VERSION 5.7 ;
  DIVIDERCHAR "/" ;
  BUSBITCHARS "[]" ;
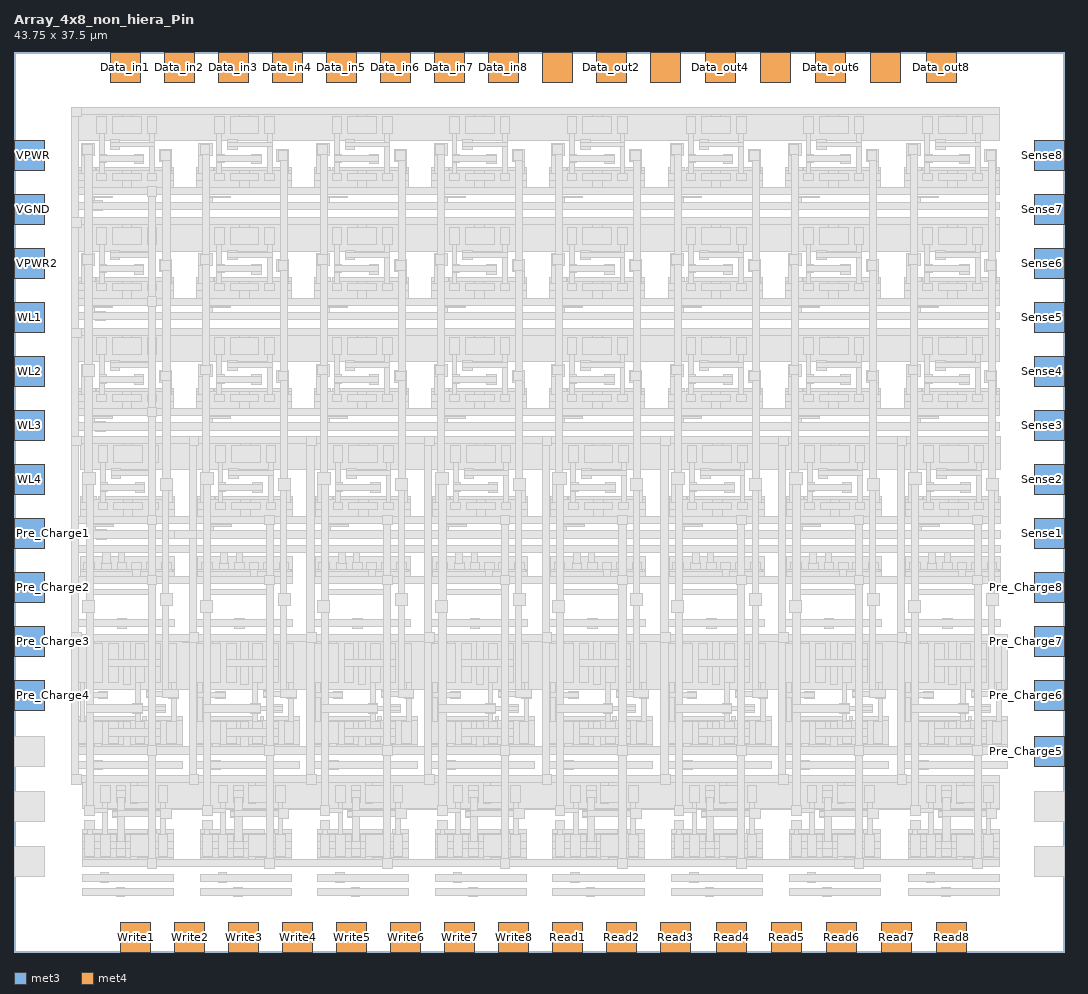
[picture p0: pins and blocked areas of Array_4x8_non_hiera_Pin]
MACRO Array_4x8_non_hiera_Pin
  CLASS BLOCK ;
  FOREIGN Array_4x8_non_hiera_Pin ;
  ORIGIN 2.4 2.3 ;
  SIZE 43.75 BY 37.5 ;
  PIN VPWR
    USE POWER ;
    PORT
      LAYER met3 ;
        RECT -2.4 30.25 -1.15 31.5 ;
    END
  END VPWR
  PIN VGND
    USE GROUND ;
    PORT
      LAYER met3 ;
        RECT -2.4 28 -1.15 29.25 ;
    END
  END VGND
  PIN VPWR2
    USE POWER ;
    PORT
      LAYER met3 ;
        RECT -2.4 25.75 -1.15 27 ;
    END
  END VPWR2
  PIN WL1
    PORT
      LAYER met3 ;
        RECT -2.4 23.5 -1.15 24.75 ;
    END
  END WL1
  PIN WL2
    PORT
      LAYER met3 ;
        RECT -2.4 21.25 -1.15 22.5 ;
    END
  END WL2
  PIN WL3
    PORT
      LAYER met3 ;
        RECT -2.4 19 -1.15 20.25 ;
    END
  END WL3
  PIN WL4
    PORT
      LAYER met3 ;
        RECT -2.4 16.75 -1.15 18 ;
    END
  END WL4
  PIN Pre_Charge1
    PORT
      LAYER met3 ;
        RECT -2.4 14.5 -1.15 15.75 ;
    END
  END Pre_Charge1
  PIN Pre_Charge2
    PORT
      LAYER met3 ;
        RECT -2.4 12.25 -1.15 13.5 ;
    END
  END Pre_Charge2
  PIN Pre_Charge3
    PORT
      LAYER met3 ;
        RECT -2.4 10 -1.15 11.25 ;
    END
  END Pre_Charge3
  PIN Pre_Charge4
    PORT
      LAYER met3 ;
        RECT -2.4 7.75 -1.15 9 ;
    END
  END Pre_Charge4
  PIN Pre_Charge5
    PORT
      LAYER met3 ;
        RECT 40.1 5.45 41.35 6.7 ;
    END
  END Pre_Charge5
  PIN Pre_Charge6
    PORT
      LAYER met3 ;
        RECT 40.1 7.75 41.35 9 ;
    END
  END Pre_Charge6
  PIN Pre_Charge7
    PORT
      LAYER met3 ;
        RECT 40.1 10 41.35 11.25 ;
    END
  END Pre_Charge7
  PIN Pre_Charge8
    PORT
      LAYER met3 ;
        RECT 40.1 12.25 41.35 13.5 ;
    END
  END Pre_Charge8
  PIN Sense1
    PORT
      LAYER met3 ;
        RECT 40.1 14.5 41.35 15.75 ;
    END
  END Sense1
  PIN Sense2
    PORT
      LAYER met3 ;
        RECT 40.1 16.75 41.35 18 ;
    END
  END Sense2
  PIN Sense3
    PORT
      LAYER met3 ;
        RECT 40.1 19 41.35 20.25 ;
    END
  END Sense3
  PIN Sense4
    PORT
      LAYER met3 ;
        RECT 40.1 21.25 41.35 22.5 ;
    END
  END Sense4
  PIN Sense5
    PORT
      LAYER met3 ;
        RECT 40.1 23.5 41.35 24.75 ;
    END
  END Sense5
  PIN Sense6
    PORT
      LAYER met3 ;
        RECT 40.1 25.75 41.35 27 ;
    END
  END Sense6
  PIN Sense7
    PORT
      LAYER met3 ;
        RECT 40.1 28 41.35 29.25 ;
    END
  END Sense7
  PIN Sense8
    PORT
      LAYER met3 ;
        RECT 40.1 30.25 41.35 31.5 ;
    END
  END Sense8
  PIN Write2
    PORT
      LAYER met4 ;
        RECT 4.3 -2.3 5.55 -1.05 ;
    END
  END Write2
  PIN Write3
    PORT
      LAYER met4 ;
        RECT 6.55 -2.3 7.8 -1.05 ;
    END
  END Write3
  PIN Write4
    PORT
      LAYER met4 ;
        RECT 8.8 -2.3 10.05 -1.05 ;
    END
  END Write4
  PIN Write5
    PORT
      LAYER met4 ;
        RECT 11.05 -2.3 12.3 -1.05 ;
    END
  END Write5
  PIN Write6
    PORT
      LAYER met4 ;
        RECT 13.3 -2.3 14.55 -1.05 ;
    END
  END Write6
  PIN Write7
    PORT
      LAYER met4 ;
        RECT 15.55 -2.3 16.8 -1.05 ;
    END
  END Write7
  PIN Write8
    PORT
      LAYER met4 ;
        RECT 17.8 -2.3 19.05 -1.05 ;
    END
  END Write8
  PIN Read1
    PORT
      LAYER met4 ;
        RECT 20.05 -2.3 21.3 -1.05 ;
    END
  END Read1
  PIN Read2
    PORT
      LAYER met4 ;
        RECT 22.3 -2.3 23.55 -1.05 ;
    END
  END Read2
  PIN Read3
    PORT
      LAYER met4 ;
        RECT 24.55 -2.3 25.8 -1.05 ;
    END
  END Read3
  PIN Read4
    PORT
      LAYER met4 ;
        RECT 26.85 -2.3 28.1 -1.05 ;
    END
  END Read4
  PIN Read5
    PORT
      LAYER met4 ;
        RECT 29.15 -2.3 30.4 -1.05 ;
    END
  END Read5
  PIN Read6
    PORT
      LAYER met4 ;
        RECT 31.45 -2.3 32.7 -1.05 ;
    END
  END Read6
  PIN Read7
    PORT
      LAYER met4 ;
        RECT 33.75 -2.3 35 -1.05 ;
    END
  END Read7
  PIN Read8
    PORT
      LAYER met4 ;
        RECT 36.05 -2.3 37.3 -1.05 ;
    END
  END Read8
  PIN Data_in3
    PORT
      LAYER met4 ;
        RECT 6.1 33.95 7.35 35.2 ;
    END
  END Data_in3
  PIN Data_in5
    PORT
      LAYER met4 ;
        RECT 10.6 33.95 11.85 35.2 ;
    END
  END Data_in5
  PIN Data_in6
    PORT
      LAYER met4 ;
        RECT 12.85 33.95 14.1 35.2 ;
    END
  END Data_in6
  PIN Data_in7
    PORT
      LAYER met4 ;
        RECT 15.1 33.95 16.35 35.2 ;
    END
  END Data_in7
  PIN Data_in8
    PORT
      LAYER met4 ;
        RECT 17.35 33.95 18.6 35.2 ;
    END
  END Data_in8
  PIN Data_out1
    PORT
      LAYER met4 ;
        RECT 19.6 33.95 20.85 35.2 ;
    END
  END Data_out1
  PIN Data_out2
    PORT
      LAYER met4 ;
        RECT 21.85 33.95 23.1 35.2 ;
    END
  END Data_out2
  PIN Data_out3
    PORT
      LAYER met4 ;
        RECT 24.1 33.95 25.35 35.2 ;
    END
  END Data_out3
  PIN Data_out4
    PORT
      LAYER met4 ;
        RECT 26.4 33.95 27.65 35.2 ;
    END
  END Data_out4
  PIN Data_out5
    PORT
      LAYER met4 ;
        RECT 28.7 33.95 29.95 35.2 ;
    END
  END Data_out5
  PIN Data_out6
    PORT
      LAYER met4 ;
        RECT 31 33.95 32.25 35.2 ;
    END
  END Data_out6
  PIN Data_out8
    PORT
      LAYER met4 ;
        RECT 35.6 33.95 36.85 35.2 ;
    END
  END Data_out8
  PIN Write1
    PORT
      LAYER met4 ;
        RECT 2.05 -2.3 3.3 -1.05 ;
    END
  END Write1
  PIN Data_in1
    PORT
      LAYER met4 ;
        RECT 1.6 33.95 2.85 35.2 ;
    END
  END Data_in1
  PIN Data_in2
    PORT
      LAYER met4 ;
        RECT 3.85 33.95 5.1 35.2 ;
    END
  END Data_in2
  PIN Data_in4
    PORT
      LAYER met4 ;
        RECT 8.35 33.95 9.6 35.2 ;
    END
  END Data_in4
  PIN Data_out7
    PORT
      LAYER met4 ;
        RECT 33.3 33.95 34.55 35.2 ;
    END
  END Data_out7
  OBS
      LAYER nwell ;
        RECT 0.3 31.5 38.65 32.8 ;
      LAYER pwell ;
        RECT 0.3 30.25 1 30.4 ;
        RECT 1.05 30.25 4.25 30.4 ;
        RECT 0.3 29.55 4.25 30.25 ;
        RECT 5.2 30.25 5.9 30.4 ;
        RECT 5.95 30.25 9.15 30.4 ;
        RECT 5.2 29.55 9.15 30.25 ;
        RECT 10.1 30.25 10.8 30.4 ;
        RECT 10.85 30.25 14.05 30.4 ;
        RECT 10.1 29.55 14.05 30.25 ;
        RECT 15 30.25 15.7 30.4 ;
        RECT 15.75 30.25 18.95 30.4 ;
        RECT 15 29.55 18.95 30.25 ;
        RECT 19.9 30.25 20.6 30.4 ;
        RECT 20.65 30.25 23.85 30.4 ;
        RECT 19.9 29.55 23.85 30.25 ;
        RECT 24.85 30.25 25.55 30.4 ;
        RECT 25.6 30.25 28.8 30.4 ;
        RECT 24.85 29.55 28.8 30.25 ;
        RECT 29.75 30.25 30.45 30.4 ;
        RECT 30.5 30.25 33.7 30.4 ;
        RECT 29.75 29.55 33.7 30.25 ;
        RECT 34.7 30.25 35.4 30.4 ;
        RECT 35.45 30.25 38.65 30.4 ;
        RECT 34.7 29.55 38.65 30.25 ;
        RECT 0.3 29.3 38.65 29.55 ;
        RECT 0.3 29.25 2.8 29.3 ;
        RECT 3.4 29.25 7.7 29.3 ;
        RECT 8.3 29.25 12.6 29.3 ;
        RECT 13.2 29.25 17.5 29.3 ;
        RECT 18.1 29.25 22.4 29.3 ;
        RECT 23 29.25 27.35 29.3 ;
        RECT 27.95 29.25 32.25 29.3 ;
        RECT 32.85 29.25 37.2 29.3 ;
        RECT 37.8 29.25 38.65 29.3 ;
        RECT 0.7 29.15 1.7 29.2 ;
        RECT 5.6 29.15 6.6 29.2 ;
        RECT 10.5 29.15 11.5 29.2 ;
        RECT 15.4 29.15 16.4 29.2 ;
        RECT 20.3 29.15 21.3 29.2 ;
        RECT 25.25 29.15 26.25 29.2 ;
        RECT 30.15 29.15 31.15 29.2 ;
        RECT 35.1 29.15 36.1 29.2 ;
        RECT 0.8 28.9 0.95 29.15 ;
        RECT 5.7 28.9 5.85 29.15 ;
        RECT 10.6 28.9 10.75 29.15 ;
        RECT 15.5 28.9 15.65 29.15 ;
        RECT 20.4 28.9 20.55 29.15 ;
        RECT 25.35 28.9 25.5 29.15 ;
        RECT 30.25 28.9 30.4 29.15 ;
        RECT 35.2 28.9 35.35 29.15 ;
      LAYER nwell ;
        RECT 0.3 26.9 38.65 28.2 ;
      LAYER pwell ;
        RECT 0.3 25.65 1 25.8 ;
        RECT 1.05 25.65 4.25 25.8 ;
        RECT 0.3 24.95 4.25 25.65 ;
        RECT 5.2 25.65 5.9 25.8 ;
        RECT 5.95 25.65 9.15 25.8 ;
        RECT 5.2 24.95 9.15 25.65 ;
        RECT 10.1 25.65 10.8 25.8 ;
        RECT 10.85 25.65 14.05 25.8 ;
        RECT 10.1 24.95 14.05 25.65 ;
        RECT 15 25.65 15.7 25.8 ;
        RECT 15.75 25.65 18.95 25.8 ;
        RECT 15 24.95 18.95 25.65 ;
        RECT 19.9 25.65 20.6 25.8 ;
        RECT 20.65 25.65 23.85 25.8 ;
        RECT 19.9 24.95 23.85 25.65 ;
        RECT 24.85 25.65 25.55 25.8 ;
        RECT 25.6 25.65 28.8 25.8 ;
        RECT 24.85 24.95 28.8 25.65 ;
        RECT 29.75 25.65 30.45 25.8 ;
        RECT 30.5 25.65 33.7 25.8 ;
        RECT 29.75 24.95 33.7 25.65 ;
        RECT 34.7 25.65 35.4 25.8 ;
        RECT 35.45 25.65 38.65 25.8 ;
        RECT 34.7 24.95 38.65 25.65 ;
        RECT 0.3 24.7 38.65 24.95 ;
        RECT 0.3 24.65 2.8 24.7 ;
        RECT 3.4 24.65 7.7 24.7 ;
        RECT 8.3 24.65 12.6 24.7 ;
        RECT 13.2 24.65 17.5 24.7 ;
        RECT 18.1 24.65 22.4 24.7 ;
        RECT 23 24.65 27.35 24.7 ;
        RECT 27.95 24.65 32.25 24.7 ;
        RECT 32.85 24.65 37.2 24.7 ;
        RECT 37.8 24.65 38.65 24.7 ;
        RECT 0.7 24.55 1.7 24.6 ;
        RECT 5.6 24.55 6.6 24.6 ;
        RECT 10.5 24.55 11.5 24.6 ;
        RECT 15.4 24.55 16.4 24.6 ;
        RECT 20.3 24.55 21.3 24.6 ;
        RECT 25.25 24.55 26.25 24.6 ;
        RECT 30.15 24.55 31.15 24.6 ;
        RECT 35.1 24.55 36.1 24.6 ;
        RECT 0.8 24.3 0.95 24.55 ;
        RECT 5.7 24.3 5.85 24.55 ;
        RECT 10.6 24.3 10.75 24.55 ;
        RECT 15.5 24.3 15.65 24.55 ;
        RECT 20.4 24.3 20.55 24.55 ;
        RECT 25.35 24.3 25.5 24.55 ;
        RECT 30.25 24.3 30.4 24.55 ;
        RECT 35.2 24.3 35.35 24.55 ;
      LAYER nwell ;
        RECT 0.3 22.3 38.65 23.6 ;
      LAYER pwell ;
        RECT 0.3 21.05 1 21.2 ;
        RECT 1.05 21.05 4.25 21.2 ;
        RECT 0.3 20.35 4.25 21.05 ;
        RECT 5.2 21.05 5.9 21.2 ;
        RECT 5.95 21.05 9.15 21.2 ;
        RECT 5.2 20.35 9.15 21.05 ;
        RECT 10.1 21.05 10.8 21.2 ;
        RECT 10.85 21.05 14.05 21.2 ;
        RECT 10.1 20.35 14.05 21.05 ;
        RECT 15 21.05 15.7 21.2 ;
        RECT 15.75 21.05 18.95 21.2 ;
        RECT 15 20.35 18.95 21.05 ;
        RECT 19.9 21.05 20.6 21.2 ;
        RECT 20.65 21.05 23.85 21.2 ;
        RECT 19.9 20.35 23.85 21.05 ;
        RECT 24.85 21.05 25.55 21.2 ;
        RECT 25.6 21.05 28.8 21.2 ;
        RECT 24.85 20.35 28.8 21.05 ;
        RECT 29.75 21.05 30.45 21.2 ;
        RECT 30.5 21.05 33.7 21.2 ;
        RECT 29.75 20.35 33.7 21.05 ;
        RECT 34.7 21.05 35.4 21.2 ;
        RECT 35.45 21.05 38.65 21.2 ;
        RECT 34.7 20.35 38.65 21.05 ;
        RECT 0.3 20.1 38.65 20.35 ;
        RECT 0.3 20.05 2.8 20.1 ;
        RECT 3.4 20.05 7.7 20.1 ;
        RECT 8.3 20.05 12.6 20.1 ;
        RECT 13.2 20.05 17.5 20.1 ;
        RECT 18.1 20.05 22.4 20.1 ;
        RECT 23 20.05 27.35 20.1 ;
        RECT 27.95 20.05 32.25 20.1 ;
        RECT 32.85 20.05 37.2 20.1 ;
        RECT 37.8 20.05 38.65 20.1 ;
        RECT 0.7 19.95 1.7 20 ;
        RECT 5.6 19.95 6.6 20 ;
        RECT 10.5 19.95 11.5 20 ;
        RECT 15.4 19.95 16.4 20 ;
        RECT 20.3 19.95 21.3 20 ;
        RECT 25.25 19.95 26.25 20 ;
        RECT 30.15 19.95 31.15 20 ;
        RECT 35.1 19.95 36.1 20 ;
        RECT 0.8 19.7 0.95 19.95 ;
        RECT 5.7 19.7 5.85 19.95 ;
        RECT 10.6 19.7 10.75 19.95 ;
        RECT 15.5 19.7 15.65 19.95 ;
        RECT 20.4 19.7 20.55 19.95 ;
        RECT 25.35 19.7 25.5 19.95 ;
        RECT 30.25 19.7 30.4 19.95 ;
        RECT 35.2 19.7 35.35 19.95 ;
      LAYER nwell ;
        RECT 0.35 17.8 38.7 19.1 ;
      LAYER pwell ;
        RECT 4.05 16.75 4.2 16.95 ;
        RECT 8.95 16.75 9.1 16.95 ;
        RECT 13.85 16.75 14 16.95 ;
        RECT 18.75 16.75 18.9 16.95 ;
        RECT 23.65 16.75 23.8 16.95 ;
        RECT 28.6 16.75 28.75 16.95 ;
        RECT 33.5 16.75 33.65 16.95 ;
        RECT 38.45 16.75 38.6 16.95 ;
        RECT 0.35 16.55 1.05 16.7 ;
        RECT 1.1 16.55 4.3 16.7 ;
        RECT 0.35 15.85 4.3 16.55 ;
        RECT 5.25 16.55 5.95 16.7 ;
        RECT 6 16.55 9.2 16.7 ;
        RECT 5.25 15.85 9.2 16.55 ;
        RECT 10.15 16.55 10.85 16.7 ;
        RECT 10.9 16.55 14.1 16.7 ;
        RECT 10.15 15.85 14.1 16.55 ;
        RECT 15.05 16.55 15.75 16.7 ;
        RECT 15.8 16.55 19 16.7 ;
        RECT 15.05 15.85 19 16.55 ;
        RECT 19.95 16.55 20.65 16.7 ;
        RECT 20.7 16.55 23.9 16.7 ;
        RECT 19.95 15.85 23.9 16.55 ;
        RECT 24.9 16.55 25.6 16.7 ;
        RECT 25.65 16.55 28.85 16.7 ;
        RECT 24.9 15.85 28.85 16.55 ;
        RECT 29.8 16.55 30.5 16.7 ;
        RECT 30.55 16.55 33.75 16.7 ;
        RECT 29.8 15.85 33.75 16.55 ;
        RECT 34.75 16.55 35.45 16.7 ;
        RECT 35.5 16.55 38.7 16.7 ;
        RECT 34.75 15.85 38.7 16.55 ;
        RECT 0 15.6 38.7 15.85 ;
        RECT 0 15.55 2.85 15.6 ;
        RECT 3.45 15.55 7.75 15.6 ;
        RECT 8.35 15.55 12.65 15.6 ;
        RECT 13.25 15.55 17.55 15.6 ;
        RECT 18.15 15.55 22.45 15.6 ;
        RECT 23.05 15.55 27.4 15.6 ;
        RECT 28 15.55 32.3 15.6 ;
        RECT 32.9 15.55 37.25 15.6 ;
        RECT 37.85 15.55 38.7 15.6 ;
        RECT 0.75 15.45 1.75 15.5 ;
        RECT 5.65 15.45 6.65 15.5 ;
        RECT 10.55 15.45 11.55 15.5 ;
        RECT 15.45 15.45 16.45 15.5 ;
        RECT 20.35 15.45 21.35 15.5 ;
        RECT 25.3 15.45 26.3 15.5 ;
        RECT 30.2 15.45 31.2 15.5 ;
        RECT 35.15 15.45 36.15 15.5 ;
        RECT 0.85 15.2 1 15.45 ;
        RECT 5.75 15.2 5.9 15.45 ;
        RECT 10.65 15.2 10.8 15.45 ;
        RECT 15.55 15.2 15.7 15.45 ;
        RECT 20.45 15.2 20.6 15.45 ;
        RECT 25.4 15.2 25.55 15.45 ;
        RECT 30.3 15.2 30.45 15.45 ;
        RECT 35.25 15.2 35.4 15.45 ;
        RECT 1.3 14.2 1.6 14.35 ;
        RECT 6.2 14.2 6.5 14.35 ;
        RECT 11.1 14.2 11.4 14.35 ;
        RECT 16 14.2 16.3 14.35 ;
        RECT 20.9 14.2 21.2 14.35 ;
        RECT 25.85 14.2 26.15 14.35 ;
        RECT 30.75 14.2 31.05 14.35 ;
        RECT 35.7 14.2 36 14.35 ;
        RECT 0.35 13.65 4.3 14.2 ;
        RECT 0.35 13.55 4.2 13.65 ;
        RECT 4.25 13.55 4.3 13.65 ;
        RECT 0.35 13.3 4.3 13.55 ;
        RECT 5.25 13.65 9.2 14.2 ;
        RECT 5.25 13.55 9.1 13.65 ;
        RECT 9.15 13.55 9.2 13.65 ;
        RECT 5.25 13.3 9.2 13.55 ;
        RECT 10.15 13.65 14.1 14.2 ;
        RECT 10.15 13.55 14 13.65 ;
        RECT 14.05 13.55 14.1 13.65 ;
        RECT 10.15 13.3 14.1 13.55 ;
        RECT 15.05 13.65 19 14.2 ;
        RECT 15.05 13.55 18.9 13.65 ;
        RECT 18.95 13.55 19 13.65 ;
        RECT 15.05 13.3 19 13.55 ;
        RECT 19.95 13.65 23.9 14.2 ;
        RECT 19.95 13.55 23.8 13.65 ;
        RECT 23.85 13.55 23.9 13.65 ;
        RECT 19.95 13.3 23.9 13.55 ;
        RECT 24.9 13.65 28.85 14.2 ;
        RECT 24.9 13.55 28.75 13.65 ;
        RECT 28.8 13.55 28.85 13.65 ;
        RECT 24.9 13.3 28.85 13.55 ;
        RECT 29.8 13.65 33.75 14.2 ;
        RECT 29.8 13.55 33.65 13.65 ;
        RECT 33.7 13.55 33.75 13.65 ;
        RECT 29.8 13.3 33.75 13.55 ;
        RECT 34.75 13.65 38.7 14.2 ;
        RECT 34.75 13.55 38.6 13.65 ;
        RECT 38.65 13.55 38.7 13.65 ;
        RECT 34.75 13.3 38.7 13.55 ;
        RECT 1.1 13.25 1.15 13.3 ;
        RECT 4.05 13.1 4.1 13.3 ;
        RECT 6 13.25 6.05 13.3 ;
        RECT 8.95 13.1 9 13.3 ;
        RECT 10.9 13.25 10.95 13.3 ;
        RECT 13.85 13.1 13.9 13.3 ;
        RECT 15.8 13.25 15.85 13.3 ;
        RECT 18.75 13.1 18.8 13.3 ;
        RECT 20.7 13.25 20.75 13.3 ;
        RECT 23.65 13.1 23.7 13.3 ;
        RECT 25.65 13.25 25.7 13.3 ;
        RECT 28.6 13.1 28.65 13.3 ;
        RECT 30.55 13.25 30.6 13.3 ;
        RECT 33.5 13.1 33.55 13.3 ;
        RECT 35.5 13.25 35.55 13.3 ;
        RECT 38.45 13.1 38.5 13.3 ;
      LAYER nwell ;
        RECT 0 8.65 39 10.85 ;
      LAYER pwell ;
        RECT 0 7.35 2.75 7.5 ;
        RECT 2.95 7.35 3.1 7.5 ;
        RECT 3.25 7.35 4.6 7.5 ;
        RECT 0 7.3 2.1 7.35 ;
        RECT 0 6.35 2.15 7.3 ;
        RECT 2.45 6.35 4.6 7.35 ;
        RECT 0 6.2 4.6 6.35 ;
        RECT 0 6.05 0.1 6.2 ;
        RECT 0.25 6.05 4.6 6.2 ;
        RECT 4.9 7.35 7.65 7.5 ;
        RECT 7.85 7.35 8 7.5 ;
        RECT 8.15 7.35 9.5 7.5 ;
        RECT 4.9 7.3 7 7.35 ;
        RECT 4.9 6.35 7.05 7.3 ;
        RECT 7.35 6.35 9.5 7.35 ;
        RECT 4.9 6.2 9.5 6.35 ;
        RECT 4.9 6.05 5 6.2 ;
        RECT 5.15 6.05 9.5 6.2 ;
        RECT 9.8 7.35 12.55 7.5 ;
        RECT 12.75 7.35 12.9 7.5 ;
        RECT 13.05 7.35 14.4 7.5 ;
        RECT 9.8 7.3 11.9 7.35 ;
        RECT 9.8 6.35 11.95 7.3 ;
        RECT 12.25 6.35 14.4 7.35 ;
        RECT 9.8 6.2 14.4 6.35 ;
        RECT 9.8 6.05 9.9 6.2 ;
        RECT 10.05 6.05 14.4 6.2 ;
        RECT 14.7 7.35 17.45 7.5 ;
        RECT 17.65 7.35 17.8 7.5 ;
        RECT 17.95 7.35 19.3 7.5 ;
        RECT 14.7 7.3 16.8 7.35 ;
        RECT 14.7 6.35 16.85 7.3 ;
        RECT 17.15 6.35 19.3 7.35 ;
        RECT 14.7 6.2 19.3 6.35 ;
        RECT 14.7 6.05 14.8 6.2 ;
        RECT 14.95 6.05 19.3 6.2 ;
        RECT 19.6 7.35 22.35 7.5 ;
        RECT 22.55 7.35 22.7 7.5 ;
        RECT 22.85 7.35 24.2 7.5 ;
        RECT 19.6 7.3 21.7 7.35 ;
        RECT 19.6 6.35 21.75 7.3 ;
        RECT 22.05 6.35 24.2 7.35 ;
        RECT 19.6 6.25 24.2 6.35 ;
        RECT 24.55 7.35 27.3 7.5 ;
        RECT 27.5 7.35 27.65 7.5 ;
        RECT 27.8 7.35 29.15 7.5 ;
        RECT 24.55 7.3 26.65 7.35 ;
        RECT 24.55 6.35 26.7 7.3 ;
        RECT 27 6.35 29.15 7.35 ;
        RECT 24.55 6.25 29.15 6.35 ;
        RECT 19.6 6.2 29.15 6.25 ;
        RECT 19.6 6.05 19.7 6.2 ;
        RECT 19.85 6.05 24.65 6.2 ;
        RECT 24.8 6.05 29.15 6.2 ;
        RECT 29.45 7.35 32.2 7.5 ;
        RECT 32.4 7.35 32.55 7.5 ;
        RECT 32.7 7.35 34.05 7.5 ;
        RECT 29.45 7.3 31.55 7.35 ;
        RECT 29.45 6.35 31.6 7.3 ;
        RECT 31.9 6.35 34.05 7.35 ;
        RECT 29.45 6.2 34.05 6.35 ;
        RECT 29.45 6.05 29.55 6.2 ;
        RECT 29.7 6.05 34.05 6.2 ;
        RECT 34.4 7.35 37.15 7.5 ;
        RECT 37.35 7.35 37.5 7.5 ;
        RECT 37.65 7.35 39 7.5 ;
        RECT 34.4 7.3 36.5 7.35 ;
        RECT 34.4 6.35 36.55 7.3 ;
        RECT 36.85 6.35 39 7.35 ;
        RECT 34.4 6.2 39 6.35 ;
        RECT 34.4 6.05 34.5 6.2 ;
        RECT 34.65 6.05 39 6.2 ;
        RECT 1.65 6 4.6 6.05 ;
        RECT 6.55 6 9.5 6.05 ;
        RECT 11.45 6 14.4 6.05 ;
        RECT 16.35 6 19.3 6.05 ;
        RECT 21.25 6 24.55 6.05 ;
        RECT 26.2 6 29.15 6.05 ;
        RECT 31.1 6 34.05 6.05 ;
        RECT 36.05 6 39 6.05 ;
        RECT 24.2 5.95 24.55 6 ;
      LAYER nwell ;
        RECT 0.45 3.7 38.65 4.95 ;
        RECT 0.55 3.65 38.65 3.7 ;
      LAYER pwell ;
        RECT 0.45 2.65 3.15 2.8 ;
        RECT 3.25 2.65 3.4 2.8 ;
        RECT 3.55 2.65 4.25 2.8 ;
        RECT 0.45 2.6 2.4 2.65 ;
        RECT 0.45 2.3 2.45 2.6 ;
        RECT 2.75 2.3 4.25 2.65 ;
        RECT 0.45 2 4.25 2.3 ;
        RECT 0.45 1.65 2.45 2 ;
        RECT 2.75 1.65 4.25 2 ;
        RECT 0.45 1.5 4.25 1.65 ;
        RECT 0.45 1.3 1.05 1.5 ;
        RECT 1.15 1.35 4.25 1.5 ;
        RECT 1.25 1.3 1.55 1.35 ;
        RECT 1.95 1.3 4.25 1.35 ;
        RECT 5.35 2.65 8.05 2.8 ;
        RECT 8.15 2.65 8.3 2.8 ;
        RECT 8.45 2.65 9.15 2.8 ;
        RECT 5.35 2.6 7.3 2.65 ;
        RECT 5.35 2.3 7.35 2.6 ;
        RECT 7.65 2.3 9.15 2.65 ;
        RECT 5.35 2 9.15 2.3 ;
        RECT 5.35 1.65 7.35 2 ;
        RECT 7.65 1.65 9.15 2 ;
        RECT 5.35 1.5 9.15 1.65 ;
        RECT 5.35 1.3 5.95 1.5 ;
        RECT 6.05 1.35 9.15 1.5 ;
        RECT 6.15 1.3 6.45 1.35 ;
        RECT 6.85 1.3 9.15 1.35 ;
        RECT 10.25 2.65 12.95 2.8 ;
        RECT 13.05 2.65 13.2 2.8 ;
        RECT 13.35 2.65 14.05 2.8 ;
        RECT 10.25 2.6 12.2 2.65 ;
        RECT 10.25 2.3 12.25 2.6 ;
        RECT 12.55 2.3 14.05 2.65 ;
        RECT 10.25 2 14.05 2.3 ;
        RECT 10.25 1.65 12.25 2 ;
        RECT 12.55 1.65 14.05 2 ;
        RECT 10.25 1.55 14.05 1.65 ;
        RECT 15.15 2.65 17.85 2.8 ;
        RECT 17.95 2.65 18.1 2.8 ;
        RECT 18.25 2.65 18.95 2.8 ;
        RECT 15.15 2.6 17.1 2.65 ;
        RECT 15.15 2.3 17.15 2.6 ;
        RECT 17.45 2.3 18.95 2.65 ;
        RECT 15.15 2 18.95 2.3 ;
        RECT 15.15 1.65 17.15 2 ;
        RECT 17.45 1.65 18.95 2 ;
        RECT 15.15 1.55 18.95 1.65 ;
        RECT 10.25 1.5 18.95 1.55 ;
        RECT 10.25 1.3 10.85 1.5 ;
        RECT 10.95 1.35 15.75 1.5 ;
        RECT 15.85 1.35 18.95 1.5 ;
        RECT 11.05 1.3 11.35 1.35 ;
        RECT 11.75 1.3 15.75 1.35 ;
        RECT 15.95 1.3 16.25 1.35 ;
        RECT 16.65 1.3 18.95 1.35 ;
        RECT 20.05 2.65 22.75 2.8 ;
        RECT 22.85 2.65 23 2.8 ;
        RECT 23.15 2.65 23.85 2.8 ;
        RECT 20.05 2.6 22 2.65 ;
        RECT 20.05 2.3 22.05 2.6 ;
        RECT 22.35 2.3 23.85 2.65 ;
        RECT 20.05 2 23.85 2.3 ;
        RECT 20.05 1.65 22.05 2 ;
        RECT 22.35 1.65 23.85 2 ;
        RECT 20.05 1.5 23.85 1.65 ;
        RECT 20.05 1.3 20.65 1.5 ;
        RECT 20.75 1.35 23.85 1.5 ;
        RECT 20.85 1.3 21.15 1.35 ;
        RECT 21.55 1.3 23.85 1.35 ;
        RECT 25 2.65 27.7 2.8 ;
        RECT 27.8 2.65 27.95 2.8 ;
        RECT 28.1 2.65 28.8 2.8 ;
        RECT 25 2.6 26.95 2.65 ;
        RECT 25 2.3 27 2.6 ;
        RECT 27.3 2.3 28.8 2.65 ;
        RECT 25 2 28.8 2.3 ;
        RECT 25 1.65 27 2 ;
        RECT 27.3 1.65 28.8 2 ;
        RECT 25 1.5 28.8 1.65 ;
        RECT 25 1.3 25.6 1.5 ;
        RECT 25.7 1.35 28.8 1.5 ;
        RECT 25.8 1.3 26.1 1.35 ;
        RECT 26.5 1.3 28.8 1.35 ;
        RECT 29.9 2.65 32.6 2.8 ;
        RECT 32.7 2.65 32.85 2.8 ;
        RECT 33 2.65 33.7 2.8 ;
        RECT 29.9 2.6 31.85 2.65 ;
        RECT 29.9 2.3 31.9 2.6 ;
        RECT 32.2 2.3 33.7 2.65 ;
        RECT 29.9 2 33.7 2.3 ;
        RECT 29.9 1.65 31.9 2 ;
        RECT 32.2 1.65 33.7 2 ;
        RECT 29.9 1.5 33.7 1.65 ;
        RECT 29.9 1.3 30.5 1.5 ;
        RECT 30.6 1.35 33.7 1.5 ;
        RECT 30.7 1.3 31 1.35 ;
        RECT 31.4 1.3 33.7 1.35 ;
        RECT 34.85 2.65 37.55 2.8 ;
        RECT 37.65 2.65 37.8 2.8 ;
        RECT 37.95 2.65 38.65 2.8 ;
        RECT 34.85 2.6 36.8 2.65 ;
        RECT 34.85 2.3 36.85 2.6 ;
        RECT 37.15 2.3 38.65 2.65 ;
        RECT 34.85 2 38.65 2.3 ;
        RECT 34.85 1.65 36.85 2 ;
        RECT 37.15 1.65 38.65 2 ;
        RECT 34.85 1.5 38.65 1.65 ;
        RECT 34.85 1.3 35.45 1.5 ;
        RECT 35.55 1.35 38.65 1.5 ;
        RECT 35.65 1.3 35.95 1.35 ;
        RECT 36.35 1.3 38.65 1.35 ;
        RECT 14.05 1.25 15.15 1.3 ;
      LAYER li1 ;
        RECT 2.1 32.5 2.5 32.9 ;
        RECT 7 32.5 7.4 32.9 ;
        RECT 11.9 32.5 12.3 32.9 ;
        RECT 16.8 32.5 17.2 32.9 ;
        RECT 21.7 32.5 22.1 32.9 ;
        RECT 26.65 32.5 27.05 32.9 ;
        RECT 31.55 32.5 31.95 32.9 ;
        RECT 36.5 32.5 36.9 32.9 ;
        RECT 1.05 31.8 1.45 32.5 ;
        RECT 1.7 31.8 2.9 32.5 ;
        RECT 3.15 31.8 3.55 32.5 ;
        RECT 5.95 31.8 6.35 32.5 ;
        RECT 6.6 31.8 7.8 32.5 ;
        RECT 8.05 31.8 8.45 32.5 ;
        RECT 10.85 31.8 11.25 32.5 ;
        RECT 11.5 31.8 12.7 32.5 ;
        RECT 12.95 31.8 13.35 32.5 ;
        RECT 15.75 31.8 16.15 32.5 ;
        RECT 16.4 31.8 17.6 32.5 ;
        RECT 17.85 31.8 18.25 32.5 ;
        RECT 20.65 31.8 21.05 32.5 ;
        RECT 21.3 31.8 22.5 32.5 ;
        RECT 22.75 31.8 23.15 32.5 ;
        RECT 25.6 31.8 26 32.5 ;
        RECT 26.25 31.8 27.45 32.5 ;
        RECT 27.7 31.8 28.1 32.5 ;
        RECT 30.5 31.8 30.9 32.5 ;
        RECT 31.15 31.8 32.35 32.5 ;
        RECT 32.6 31.8 33 32.5 ;
        RECT 35.45 31.8 35.85 32.5 ;
        RECT 36.1 31.8 37.3 32.5 ;
        RECT 37.55 31.8 37.95 32.5 ;
        RECT 0.4 30.9 0.95 31.4 ;
        RECT 1.15 30.95 1.35 31.8 ;
        RECT 1.6 31.45 2 31.55 ;
        RECT 3.25 31.45 3.45 31.8 ;
        RECT 1.6 31.25 3.45 31.45 ;
        RECT 1.6 31.15 2 31.25 ;
        RECT 1.15 30.9 1.45 30.95 ;
        RECT 2.6 30.9 3 30.95 ;
        RECT 0.4 30.15 0.6 30.9 ;
        RECT 1.15 30.65 3 30.9 ;
        RECT 1.15 30.6 1.45 30.65 ;
        RECT 1.15 30.15 1.35 30.6 ;
        RECT 2.6 30.55 3 30.65 ;
        RECT 2.1 30.15 2.5 30.25 ;
        RECT 3.25 30.15 3.45 31.25 ;
        RECT 3.65 30.65 4.15 31.15 ;
        RECT 3.95 30.15 4.15 30.65 ;
        RECT 5.3 30.9 5.85 31.4 ;
        RECT 6.05 30.95 6.25 31.8 ;
        RECT 6.5 31.45 6.9 31.55 ;
        RECT 8.15 31.45 8.35 31.8 ;
        RECT 6.5 31.25 8.35 31.45 ;
        RECT 6.5 31.15 6.9 31.25 ;
        RECT 6.05 30.9 6.35 30.95 ;
        RECT 7.5 30.9 7.9 30.95 ;
        RECT 5.3 30.15 5.5 30.9 ;
        RECT 6.05 30.65 7.9 30.9 ;
        RECT 6.05 30.6 6.35 30.65 ;
        RECT 6.05 30.15 6.25 30.6 ;
        RECT 7.5 30.55 7.9 30.65 ;
        RECT 7 30.15 7.4 30.25 ;
        RECT 8.15 30.15 8.35 31.25 ;
        RECT 8.55 30.65 9.05 31.15 ;
        RECT 8.85 30.15 9.05 30.65 ;
        RECT 10.2 30.9 10.75 31.4 ;
        RECT 10.95 30.95 11.15 31.8 ;
        RECT 11.4 31.45 11.8 31.55 ;
        RECT 13.05 31.45 13.25 31.8 ;
        RECT 11.4 31.25 13.25 31.45 ;
        RECT 11.4 31.15 11.8 31.25 ;
        RECT 10.95 30.9 11.25 30.95 ;
        RECT 12.4 30.9 12.8 30.95 ;
        RECT 10.2 30.15 10.4 30.9 ;
        RECT 10.95 30.65 12.8 30.9 ;
        RECT 10.95 30.6 11.25 30.65 ;
        RECT 10.95 30.15 11.15 30.6 ;
        RECT 12.4 30.55 12.8 30.65 ;
        RECT 11.9 30.15 12.3 30.25 ;
        RECT 13.05 30.15 13.25 31.25 ;
        RECT 13.45 30.65 13.95 31.15 ;
        RECT 13.75 30.15 13.95 30.65 ;
        RECT 15.1 30.9 15.65 31.4 ;
        RECT 15.85 30.95 16.05 31.8 ;
        RECT 16.3 31.45 16.7 31.55 ;
        RECT 17.95 31.45 18.15 31.8 ;
        RECT 16.3 31.25 18.15 31.45 ;
        RECT 16.3 31.15 16.7 31.25 ;
        RECT 15.85 30.9 16.15 30.95 ;
        RECT 17.3 30.9 17.7 30.95 ;
        RECT 15.1 30.15 15.3 30.9 ;
        RECT 15.85 30.65 17.7 30.9 ;
        RECT 15.85 30.6 16.15 30.65 ;
        RECT 15.85 30.15 16.05 30.6 ;
        RECT 17.3 30.55 17.7 30.65 ;
        RECT 16.8 30.15 17.2 30.25 ;
        RECT 17.95 30.15 18.15 31.25 ;
        RECT 18.35 30.65 18.85 31.15 ;
        RECT 18.65 30.15 18.85 30.65 ;
        RECT 20 30.9 20.55 31.4 ;
        RECT 20.75 30.95 20.95 31.8 ;
        RECT 21.2 31.45 21.6 31.55 ;
        RECT 22.85 31.45 23.05 31.8 ;
        RECT 21.2 31.25 23.05 31.45 ;
        RECT 21.2 31.15 21.6 31.25 ;
        RECT 20.75 30.9 21.05 30.95 ;
        RECT 22.2 30.9 22.6 30.95 ;
        RECT 20 30.15 20.2 30.9 ;
        RECT 20.75 30.65 22.6 30.9 ;
        RECT 20.75 30.6 21.05 30.65 ;
        RECT 20.75 30.15 20.95 30.6 ;
        RECT 22.2 30.55 22.6 30.65 ;
        RECT 21.7 30.15 22.1 30.25 ;
        RECT 22.85 30.15 23.05 31.25 ;
        RECT 23.25 30.65 23.75 31.15 ;
        RECT 23.55 30.15 23.75 30.65 ;
        RECT 24.95 30.9 25.5 31.4 ;
        RECT 25.7 30.95 25.9 31.8 ;
        RECT 26.15 31.45 26.55 31.55 ;
        RECT 27.8 31.45 28 31.8 ;
        RECT 26.15 31.25 28 31.45 ;
        RECT 26.15 31.15 26.55 31.25 ;
        RECT 25.7 30.9 26 30.95 ;
        RECT 27.15 30.9 27.55 30.95 ;
        RECT 24.95 30.15 25.15 30.9 ;
        RECT 25.7 30.65 27.55 30.9 ;
        RECT 25.7 30.6 26 30.65 ;
        RECT 25.7 30.15 25.9 30.6 ;
        RECT 27.15 30.55 27.55 30.65 ;
        RECT 26.65 30.15 27.05 30.25 ;
        RECT 27.8 30.15 28 31.25 ;
        RECT 28.2 30.65 28.7 31.15 ;
        RECT 28.5 30.15 28.7 30.65 ;
        RECT 29.85 30.9 30.4 31.4 ;
        RECT 30.6 30.95 30.8 31.8 ;
        RECT 31.05 31.45 31.45 31.55 ;
        RECT 32.7 31.45 32.9 31.8 ;
        RECT 31.05 31.25 32.9 31.45 ;
        RECT 31.05 31.15 31.45 31.25 ;
        RECT 30.6 30.9 30.9 30.95 ;
        RECT 32.05 30.9 32.45 30.95 ;
        RECT 29.85 30.15 30.05 30.9 ;
        RECT 30.6 30.65 32.45 30.9 ;
        RECT 30.6 30.6 30.9 30.65 ;
        RECT 30.6 30.15 30.8 30.6 ;
        RECT 32.05 30.55 32.45 30.65 ;
        RECT 31.55 30.15 31.95 30.25 ;
        RECT 32.7 30.15 32.9 31.25 ;
        RECT 33.1 30.65 33.6 31.15 ;
        RECT 33.4 30.15 33.6 30.65 ;
        RECT 34.8 30.9 35.35 31.4 ;
        RECT 35.55 30.95 35.75 31.8 ;
        RECT 36 31.45 36.4 31.55 ;
        RECT 37.65 31.45 37.85 31.8 ;
        RECT 36 31.25 37.85 31.45 ;
        RECT 36 31.15 36.4 31.25 ;
        RECT 35.55 30.9 35.85 30.95 ;
        RECT 37 30.9 37.4 30.95 ;
        RECT 34.8 30.15 35 30.9 ;
        RECT 35.55 30.65 37.4 30.9 ;
        RECT 35.55 30.6 35.85 30.65 ;
        RECT 35.55 30.15 35.75 30.6 ;
        RECT 37 30.55 37.4 30.65 ;
        RECT 36.5 30.15 36.9 30.25 ;
        RECT 37.65 30.15 37.85 31.25 ;
        RECT 38.05 30.65 38.55 31.15 ;
        RECT 38.35 30.15 38.55 30.65 ;
        RECT 0.3 29.85 0.75 30.15 ;
        RECT 1.05 29.85 1.45 30.15 ;
        RECT 1.7 29.85 2.9 30.15 ;
        RECT 3.15 29.85 3.55 30.15 ;
        RECT 3.85 29.85 4.25 30.15 ;
        RECT 5.2 29.85 5.65 30.15 ;
        RECT 5.95 29.85 6.35 30.15 ;
        RECT 6.6 29.85 7.8 30.15 ;
        RECT 8.05 29.85 8.45 30.15 ;
        RECT 8.75 29.85 9.15 30.15 ;
        RECT 10.1 29.85 10.55 30.15 ;
        RECT 10.85 29.85 11.25 30.15 ;
        RECT 11.5 29.85 12.7 30.15 ;
        RECT 12.95 29.85 13.35 30.15 ;
        RECT 13.65 29.85 14.05 30.15 ;
        RECT 15 29.85 15.45 30.15 ;
        RECT 15.75 29.85 16.15 30.15 ;
        RECT 16.4 29.85 17.6 30.15 ;
        RECT 17.85 29.85 18.25 30.15 ;
        RECT 18.55 29.85 18.95 30.15 ;
        RECT 19.9 29.85 20.35 30.15 ;
        RECT 20.65 29.85 21.05 30.15 ;
        RECT 21.3 29.85 22.5 30.15 ;
        RECT 22.75 29.85 23.15 30.15 ;
        RECT 23.45 29.85 23.85 30.15 ;
        RECT 24.85 29.85 25.3 30.15 ;
        RECT 25.6 29.85 26 30.15 ;
        RECT 26.25 29.85 27.45 30.15 ;
        RECT 27.7 29.85 28.1 30.15 ;
        RECT 28.4 29.85 28.8 30.15 ;
        RECT 29.75 29.85 30.2 30.15 ;
        RECT 30.5 29.85 30.9 30.15 ;
        RECT 31.15 29.85 32.35 30.15 ;
        RECT 32.6 29.85 33 30.15 ;
        RECT 33.3 29.85 33.7 30.15 ;
        RECT 34.7 29.85 35.15 30.15 ;
        RECT 35.45 29.85 35.85 30.15 ;
        RECT 36.1 29.85 37.3 30.15 ;
        RECT 37.55 29.85 37.95 30.15 ;
        RECT 38.25 29.85 38.65 30.15 ;
        RECT 2.1 29.25 2.5 29.85 ;
        RECT 7 29.25 7.4 29.85 ;
        RECT 11.9 29.25 12.3 29.85 ;
        RECT 16.8 29.25 17.2 29.85 ;
        RECT 21.7 29.25 22.1 29.85 ;
        RECT 26.65 29.25 27.05 29.85 ;
        RECT 31.55 29.25 31.95 29.85 ;
        RECT 36.5 29.25 36.9 29.85 ;
        RECT 0.9 28.95 1.3 29 ;
        RECT 0.3 28.65 38.65 28.95 ;
        RECT 0.9 28.6 1.3 28.65 ;
        RECT 2.1 27.9 2.5 28.3 ;
        RECT 7 27.9 7.4 28.3 ;
        RECT 11.9 27.9 12.3 28.3 ;
        RECT 16.8 27.9 17.2 28.3 ;
        RECT 21.7 27.9 22.1 28.3 ;
        RECT 26.65 27.9 27.05 28.3 ;
        RECT 31.55 27.9 31.95 28.3 ;
        RECT 36.5 27.9 36.9 28.3 ;
        RECT 1.05 27.2 1.45 27.9 ;
        RECT 1.7 27.2 2.9 27.9 ;
        RECT 3.15 27.2 3.55 27.9 ;
        RECT 5.95 27.2 6.35 27.9 ;
        RECT 6.6 27.2 7.8 27.9 ;
        RECT 8.05 27.2 8.45 27.9 ;
        RECT 10.85 27.2 11.25 27.9 ;
        RECT 11.5 27.2 12.7 27.9 ;
        RECT 12.95 27.2 13.35 27.9 ;
        RECT 15.75 27.2 16.15 27.9 ;
        RECT 16.4 27.2 17.6 27.9 ;
        RECT 17.85 27.2 18.25 27.9 ;
        RECT 20.65 27.2 21.05 27.9 ;
        RECT 21.3 27.2 22.5 27.9 ;
        RECT 22.75 27.2 23.15 27.9 ;
        RECT 25.6 27.2 26 27.9 ;
        RECT 26.25 27.2 27.45 27.9 ;
        RECT 27.7 27.2 28.1 27.9 ;
        RECT 30.5 27.2 30.9 27.9 ;
        RECT 31.15 27.2 32.35 27.9 ;
        RECT 32.6 27.2 33 27.9 ;
        RECT 35.45 27.2 35.85 27.9 ;
        RECT 36.1 27.2 37.3 27.9 ;
        RECT 37.55 27.2 37.95 27.9 ;
        RECT 0.4 26.3 0.95 26.8 ;
        RECT 1.15 26.35 1.35 27.2 ;
        RECT 1.6 26.85 2 26.95 ;
        RECT 3.25 26.85 3.45 27.2 ;
        RECT 1.6 26.65 3.45 26.85 ;
        RECT 1.6 26.55 2 26.65 ;
        RECT 1.15 26.3 1.45 26.35 ;
        RECT 2.6 26.3 3 26.35 ;
        RECT 0.4 25.55 0.6 26.3 ;
        RECT 1.15 26.05 3 26.3 ;
        RECT 1.15 26 1.45 26.05 ;
        RECT 1.15 25.55 1.35 26 ;
        RECT 2.6 25.95 3 26.05 ;
        RECT 2.1 25.55 2.5 25.65 ;
        RECT 3.25 25.55 3.45 26.65 ;
        RECT 3.65 26.05 4.15 26.55 ;
        RECT 3.95 25.55 4.15 26.05 ;
        RECT 5.3 26.3 5.85 26.8 ;
        RECT 6.05 26.35 6.25 27.2 ;
        RECT 6.5 26.85 6.9 26.95 ;
        RECT 8.15 26.85 8.35 27.2 ;
        RECT 6.5 26.65 8.35 26.85 ;
        RECT 6.5 26.55 6.9 26.65 ;
        RECT 6.05 26.3 6.35 26.35 ;
        RECT 7.5 26.3 7.9 26.35 ;
        RECT 5.3 25.55 5.5 26.3 ;
        RECT 6.05 26.05 7.9 26.3 ;
        RECT 6.05 26 6.35 26.05 ;
        RECT 6.05 25.55 6.25 26 ;
        RECT 7.5 25.95 7.9 26.05 ;
        RECT 7 25.55 7.4 25.65 ;
        RECT 8.15 25.55 8.35 26.65 ;
        RECT 8.55 26.05 9.05 26.55 ;
        RECT 8.85 25.55 9.05 26.05 ;
        RECT 10.2 26.3 10.75 26.8 ;
        RECT 10.95 26.35 11.15 27.2 ;
        RECT 11.4 26.85 11.8 26.95 ;
        RECT 13.05 26.85 13.25 27.2 ;
        RECT 11.4 26.65 13.25 26.85 ;
        RECT 11.4 26.55 11.8 26.65 ;
        RECT 10.95 26.3 11.25 26.35 ;
        RECT 12.4 26.3 12.8 26.35 ;
        RECT 10.2 25.55 10.4 26.3 ;
        RECT 10.95 26.05 12.8 26.3 ;
        RECT 10.95 26 11.25 26.05 ;
        RECT 10.95 25.55 11.15 26 ;
        RECT 12.4 25.95 12.8 26.05 ;
        RECT 11.9 25.55 12.3 25.65 ;
        RECT 13.05 25.55 13.25 26.65 ;
        RECT 13.45 26.05 13.95 26.55 ;
        RECT 13.75 25.55 13.95 26.05 ;
        RECT 15.1 26.3 15.65 26.8 ;
        RECT 15.85 26.35 16.05 27.2 ;
        RECT 16.3 26.85 16.7 26.95 ;
        RECT 17.95 26.85 18.15 27.2 ;
        RECT 16.3 26.65 18.15 26.85 ;
        RECT 16.3 26.55 16.7 26.65 ;
        RECT 15.85 26.3 16.15 26.35 ;
        RECT 17.3 26.3 17.7 26.35 ;
        RECT 15.1 25.55 15.3 26.3 ;
        RECT 15.85 26.05 17.7 26.3 ;
        RECT 15.85 26 16.15 26.05 ;
        RECT 15.85 25.55 16.05 26 ;
        RECT 17.3 25.95 17.7 26.05 ;
        RECT 16.8 25.55 17.2 25.65 ;
        RECT 17.95 25.55 18.15 26.65 ;
        RECT 18.35 26.05 18.85 26.55 ;
        RECT 18.65 25.55 18.85 26.05 ;
        RECT 20 26.3 20.55 26.8 ;
        RECT 20.75 26.35 20.95 27.2 ;
        RECT 21.2 26.85 21.6 26.95 ;
        RECT 22.85 26.85 23.05 27.2 ;
        RECT 21.2 26.65 23.05 26.85 ;
        RECT 21.2 26.55 21.6 26.65 ;
        RECT 20.75 26.3 21.05 26.35 ;
        RECT 22.2 26.3 22.6 26.35 ;
        RECT 20 25.55 20.2 26.3 ;
        RECT 20.75 26.05 22.6 26.3 ;
        RECT 20.75 26 21.05 26.05 ;
        RECT 20.75 25.55 20.95 26 ;
        RECT 22.2 25.95 22.6 26.05 ;
        RECT 21.7 25.55 22.1 25.65 ;
        RECT 22.85 25.55 23.05 26.65 ;
        RECT 23.25 26.05 23.75 26.55 ;
        RECT 23.55 25.55 23.75 26.05 ;
        RECT 24.95 26.3 25.5 26.8 ;
        RECT 25.7 26.35 25.9 27.2 ;
        RECT 26.15 26.85 26.55 26.95 ;
        RECT 27.8 26.85 28 27.2 ;
        RECT 26.15 26.65 28 26.85 ;
        RECT 26.15 26.55 26.55 26.65 ;
        RECT 25.7 26.3 26 26.35 ;
        RECT 27.15 26.3 27.55 26.35 ;
        RECT 24.95 25.55 25.15 26.3 ;
        RECT 25.7 26.05 27.55 26.3 ;
        RECT 25.7 26 26 26.05 ;
        RECT 25.7 25.55 25.9 26 ;
        RECT 27.15 25.95 27.55 26.05 ;
        RECT 26.65 25.55 27.05 25.65 ;
        RECT 27.8 25.55 28 26.65 ;
        RECT 28.2 26.05 28.7 26.55 ;
        RECT 28.5 25.55 28.7 26.05 ;
        RECT 29.85 26.3 30.4 26.8 ;
        RECT 30.6 26.35 30.8 27.2 ;
        RECT 31.05 26.85 31.45 26.95 ;
        RECT 32.7 26.85 32.9 27.2 ;
        RECT 31.05 26.65 32.9 26.85 ;
        RECT 31.05 26.55 31.45 26.65 ;
        RECT 30.6 26.3 30.9 26.35 ;
        RECT 32.05 26.3 32.45 26.35 ;
        RECT 29.85 25.55 30.05 26.3 ;
        RECT 30.6 26.05 32.45 26.3 ;
        RECT 30.6 26 30.9 26.05 ;
        RECT 30.6 25.55 30.8 26 ;
        RECT 32.05 25.95 32.45 26.05 ;
        RECT 31.55 25.55 31.95 25.65 ;
        RECT 32.7 25.55 32.9 26.65 ;
        RECT 33.1 26.05 33.6 26.55 ;
        RECT 33.4 25.55 33.6 26.05 ;
        RECT 34.8 26.3 35.35 26.8 ;
        RECT 35.55 26.35 35.75 27.2 ;
        RECT 36 26.85 36.4 26.95 ;
        RECT 37.65 26.85 37.85 27.2 ;
        RECT 36 26.65 37.85 26.85 ;
        RECT 36 26.55 36.4 26.65 ;
        RECT 35.55 26.3 35.85 26.35 ;
        RECT 37 26.3 37.4 26.35 ;
        RECT 34.8 25.55 35 26.3 ;
        RECT 35.55 26.05 37.4 26.3 ;
        RECT 35.55 26 35.85 26.05 ;
        RECT 35.55 25.55 35.75 26 ;
        RECT 37 25.95 37.4 26.05 ;
        RECT 36.5 25.55 36.9 25.65 ;
        RECT 37.65 25.55 37.85 26.65 ;
        RECT 38.05 26.05 38.55 26.55 ;
        RECT 38.35 25.55 38.55 26.05 ;
        RECT 0.3 25.25 0.75 25.55 ;
        RECT 1.05 25.25 1.45 25.55 ;
        RECT 1.7 25.25 2.9 25.55 ;
        RECT 3.15 25.25 3.55 25.55 ;
        RECT 3.85 25.25 4.25 25.55 ;
        RECT 5.2 25.25 5.65 25.55 ;
        RECT 5.95 25.25 6.35 25.55 ;
        RECT 6.6 25.25 7.8 25.55 ;
        RECT 8.05 25.25 8.45 25.55 ;
        RECT 8.75 25.25 9.15 25.55 ;
        RECT 10.1 25.25 10.55 25.55 ;
        RECT 10.85 25.25 11.25 25.55 ;
        RECT 11.5 25.25 12.7 25.55 ;
        RECT 12.95 25.25 13.35 25.55 ;
        RECT 13.65 25.25 14.05 25.55 ;
        RECT 15 25.25 15.45 25.55 ;
        RECT 15.75 25.25 16.15 25.55 ;
        RECT 16.4 25.25 17.6 25.55 ;
        RECT 17.85 25.25 18.25 25.55 ;
        RECT 18.55 25.25 18.95 25.55 ;
        RECT 19.9 25.25 20.35 25.55 ;
        RECT 20.65 25.25 21.05 25.55 ;
        RECT 21.3 25.25 22.5 25.55 ;
        RECT 22.75 25.25 23.15 25.55 ;
        RECT 23.45 25.25 23.85 25.55 ;
        RECT 24.85 25.25 25.3 25.55 ;
        RECT 25.6 25.25 26 25.55 ;
        RECT 26.25 25.25 27.45 25.55 ;
        RECT 27.7 25.25 28.1 25.55 ;
        RECT 28.4 25.25 28.8 25.55 ;
        RECT 29.75 25.25 30.2 25.55 ;
        RECT 30.5 25.25 30.9 25.55 ;
        RECT 31.15 25.25 32.35 25.55 ;
        RECT 32.6 25.25 33 25.55 ;
        RECT 33.3 25.25 33.7 25.55 ;
        RECT 34.7 25.25 35.15 25.55 ;
        RECT 35.45 25.25 35.85 25.55 ;
        RECT 36.1 25.25 37.3 25.55 ;
        RECT 37.55 25.25 37.95 25.55 ;
        RECT 38.25 25.25 38.65 25.55 ;
        RECT 2.1 24.65 2.5 25.25 ;
        RECT 7 24.65 7.4 25.25 ;
        RECT 11.9 24.65 12.3 25.25 ;
        RECT 16.8 24.65 17.2 25.25 ;
        RECT 21.7 24.65 22.1 25.25 ;
        RECT 26.65 24.65 27.05 25.25 ;
        RECT 31.55 24.65 31.95 25.25 ;
        RECT 36.5 24.65 36.9 25.25 ;
        RECT 1 24.35 1.4 24.4 ;
        RECT 0.3 24.05 38.65 24.35 ;
        RECT 1 24 1.4 24.05 ;
        RECT 2.1 23.3 2.5 23.7 ;
        RECT 7 23.3 7.4 23.7 ;
        RECT 11.9 23.3 12.3 23.7 ;
        RECT 16.8 23.3 17.2 23.7 ;
        RECT 21.7 23.3 22.1 23.7 ;
        RECT 26.65 23.3 27.05 23.7 ;
        RECT 31.55 23.3 31.95 23.7 ;
        RECT 36.5 23.3 36.9 23.7 ;
        RECT 1.05 22.6 1.45 23.3 ;
        RECT 1.7 22.6 2.9 23.3 ;
        RECT 3.15 22.6 3.55 23.3 ;
        RECT 5.95 22.6 6.35 23.3 ;
        RECT 6.6 22.6 7.8 23.3 ;
        RECT 8.05 22.6 8.45 23.3 ;
        RECT 10.85 22.6 11.25 23.3 ;
        RECT 11.5 22.6 12.7 23.3 ;
        RECT 12.95 22.6 13.35 23.3 ;
        RECT 15.75 22.6 16.15 23.3 ;
        RECT 16.4 22.6 17.6 23.3 ;
        RECT 17.85 22.6 18.25 23.3 ;
        RECT 20.65 22.6 21.05 23.3 ;
        RECT 21.3 22.6 22.5 23.3 ;
        RECT 22.75 22.6 23.15 23.3 ;
        RECT 25.6 22.6 26 23.3 ;
        RECT 26.25 22.6 27.45 23.3 ;
        RECT 27.7 22.6 28.1 23.3 ;
        RECT 30.5 22.6 30.9 23.3 ;
        RECT 31.15 22.6 32.35 23.3 ;
        RECT 32.6 22.6 33 23.3 ;
        RECT 35.45 22.6 35.85 23.3 ;
        RECT 36.1 22.6 37.3 23.3 ;
        RECT 37.55 22.6 37.95 23.3 ;
        RECT 0.4 21.7 0.95 22.2 ;
        RECT 1.15 21.75 1.35 22.6 ;
        RECT 1.6 22.25 2 22.35 ;
        RECT 3.25 22.25 3.45 22.6 ;
        RECT 1.6 22.05 3.45 22.25 ;
        RECT 1.6 21.95 2 22.05 ;
        RECT 1.15 21.7 1.45 21.75 ;
        RECT 2.6 21.7 3 21.75 ;
        RECT 0.4 20.95 0.6 21.7 ;
        RECT 1.15 21.45 3 21.7 ;
        RECT 1.15 21.4 1.45 21.45 ;
        RECT 1.15 20.95 1.35 21.4 ;
        RECT 2.6 21.35 3 21.45 ;
        RECT 2.1 20.95 2.5 21.05 ;
        RECT 3.25 20.95 3.45 22.05 ;
        RECT 3.65 21.45 4.15 21.95 ;
        RECT 3.95 20.95 4.15 21.45 ;
        RECT 5.3 21.7 5.85 22.2 ;
        RECT 6.05 21.75 6.25 22.6 ;
        RECT 6.5 22.25 6.9 22.35 ;
        RECT 8.15 22.25 8.35 22.6 ;
        RECT 6.5 22.05 8.35 22.25 ;
        RECT 6.5 21.95 6.9 22.05 ;
        RECT 6.05 21.7 6.35 21.75 ;
        RECT 7.5 21.7 7.9 21.75 ;
        RECT 5.3 20.95 5.5 21.7 ;
        RECT 6.05 21.45 7.9 21.7 ;
        RECT 6.05 21.4 6.35 21.45 ;
        RECT 6.05 20.95 6.25 21.4 ;
        RECT 7.5 21.35 7.9 21.45 ;
        RECT 7 20.95 7.4 21.05 ;
        RECT 8.15 20.95 8.35 22.05 ;
        RECT 8.55 21.45 9.05 21.95 ;
        RECT 8.85 20.95 9.05 21.45 ;
        RECT 10.2 21.7 10.75 22.2 ;
        RECT 10.95 21.75 11.15 22.6 ;
        RECT 11.4 22.25 11.8 22.35 ;
        RECT 13.05 22.25 13.25 22.6 ;
        RECT 11.4 22.05 13.25 22.25 ;
        RECT 11.4 21.95 11.8 22.05 ;
        RECT 10.95 21.7 11.25 21.75 ;
        RECT 12.4 21.7 12.8 21.75 ;
        RECT 10.2 20.95 10.4 21.7 ;
        RECT 10.95 21.45 12.8 21.7 ;
        RECT 10.95 21.4 11.25 21.45 ;
        RECT 10.95 20.95 11.15 21.4 ;
        RECT 12.4 21.35 12.8 21.45 ;
        RECT 11.9 20.95 12.3 21.05 ;
        RECT 13.05 20.95 13.25 22.05 ;
        RECT 13.45 21.45 13.95 21.95 ;
        RECT 13.75 20.95 13.95 21.45 ;
        RECT 15.1 21.7 15.65 22.2 ;
        RECT 15.85 21.75 16.05 22.6 ;
        RECT 16.3 22.25 16.7 22.35 ;
        RECT 17.95 22.25 18.15 22.6 ;
        RECT 16.3 22.05 18.15 22.25 ;
        RECT 16.3 21.95 16.7 22.05 ;
        RECT 15.85 21.7 16.15 21.75 ;
        RECT 17.3 21.7 17.7 21.75 ;
        RECT 15.1 20.95 15.3 21.7 ;
        RECT 15.85 21.45 17.7 21.7 ;
        RECT 15.85 21.4 16.15 21.45 ;
        RECT 15.85 20.95 16.05 21.4 ;
        RECT 17.3 21.35 17.7 21.45 ;
        RECT 16.8 20.95 17.2 21.05 ;
        RECT 17.95 20.95 18.15 22.05 ;
        RECT 18.35 21.45 18.85 21.95 ;
        RECT 18.65 20.95 18.85 21.45 ;
        RECT 20 21.7 20.55 22.2 ;
        RECT 20.75 21.75 20.95 22.6 ;
        RECT 21.2 22.25 21.6 22.35 ;
        RECT 22.85 22.25 23.05 22.6 ;
        RECT 21.2 22.05 23.05 22.25 ;
        RECT 21.2 21.95 21.6 22.05 ;
        RECT 20.75 21.7 21.05 21.75 ;
        RECT 22.2 21.7 22.6 21.75 ;
        RECT 20 20.95 20.2 21.7 ;
        RECT 20.75 21.45 22.6 21.7 ;
        RECT 20.75 21.4 21.05 21.45 ;
        RECT 20.75 20.95 20.95 21.4 ;
        RECT 22.2 21.35 22.6 21.45 ;
        RECT 21.7 20.95 22.1 21.05 ;
        RECT 22.85 20.95 23.05 22.05 ;
        RECT 23.25 21.45 23.75 21.95 ;
        RECT 23.55 20.95 23.75 21.45 ;
        RECT 24.95 21.7 25.5 22.2 ;
        RECT 25.7 21.75 25.9 22.6 ;
        RECT 26.15 22.25 26.55 22.35 ;
        RECT 27.8 22.25 28 22.6 ;
        RECT 26.15 22.05 28 22.25 ;
        RECT 26.15 21.95 26.55 22.05 ;
        RECT 25.7 21.7 26 21.75 ;
        RECT 27.15 21.7 27.55 21.75 ;
        RECT 24.95 20.95 25.15 21.7 ;
        RECT 25.7 21.45 27.55 21.7 ;
        RECT 25.7 21.4 26 21.45 ;
        RECT 25.7 20.95 25.9 21.4 ;
        RECT 27.15 21.35 27.55 21.45 ;
        RECT 26.65 20.95 27.05 21.05 ;
        RECT 27.8 20.95 28 22.05 ;
        RECT 28.2 21.45 28.7 21.95 ;
        RECT 28.5 20.95 28.7 21.45 ;
        RECT 29.85 21.7 30.4 22.2 ;
        RECT 30.6 21.75 30.8 22.6 ;
        RECT 31.05 22.25 31.45 22.35 ;
        RECT 32.7 22.25 32.9 22.6 ;
        RECT 31.05 22.05 32.9 22.25 ;
        RECT 31.05 21.95 31.45 22.05 ;
        RECT 30.6 21.7 30.9 21.75 ;
        RECT 32.05 21.7 32.45 21.75 ;
        RECT 29.85 20.95 30.05 21.7 ;
        RECT 30.6 21.45 32.45 21.7 ;
        RECT 30.6 21.4 30.9 21.45 ;
        RECT 30.6 20.95 30.8 21.4 ;
        RECT 32.05 21.35 32.45 21.45 ;
        RECT 31.55 20.95 31.95 21.05 ;
        RECT 32.7 20.95 32.9 22.05 ;
        RECT 33.1 21.45 33.6 21.95 ;
        RECT 33.4 20.95 33.6 21.45 ;
        RECT 34.8 21.7 35.35 22.2 ;
        RECT 35.55 21.75 35.75 22.6 ;
        RECT 36 22.25 36.4 22.35 ;
        RECT 37.65 22.25 37.85 22.6 ;
        RECT 36 22.05 37.85 22.25 ;
        RECT 36 21.95 36.4 22.05 ;
        RECT 35.55 21.7 35.85 21.75 ;
        RECT 37 21.7 37.4 21.75 ;
        RECT 34.8 20.95 35 21.7 ;
        RECT 35.55 21.45 37.4 21.7 ;
        RECT 35.55 21.4 35.85 21.45 ;
        RECT 35.55 20.95 35.75 21.4 ;
        RECT 37 21.35 37.4 21.45 ;
        RECT 36.5 20.95 36.9 21.05 ;
        RECT 37.65 20.95 37.85 22.05 ;
        RECT 38.05 21.45 38.55 21.95 ;
        RECT 38.35 20.95 38.55 21.45 ;
        RECT 0.3 20.65 0.75 20.95 ;
        RECT 1.05 20.65 1.45 20.95 ;
        RECT 1.7 20.65 2.9 20.95 ;
        RECT 3.15 20.65 3.55 20.95 ;
        RECT 3.85 20.65 4.25 20.95 ;
        RECT 5.2 20.65 5.65 20.95 ;
        RECT 5.95 20.65 6.35 20.95 ;
        RECT 6.6 20.65 7.8 20.95 ;
        RECT 8.05 20.65 8.45 20.95 ;
        RECT 8.75 20.65 9.15 20.95 ;
        RECT 10.1 20.65 10.55 20.95 ;
        RECT 10.85 20.65 11.25 20.95 ;
        RECT 11.5 20.65 12.7 20.95 ;
        RECT 12.95 20.65 13.35 20.95 ;
        RECT 13.65 20.65 14.05 20.95 ;
        RECT 15 20.65 15.45 20.95 ;
        RECT 15.75 20.65 16.15 20.95 ;
        RECT 16.4 20.65 17.6 20.95 ;
        RECT 17.85 20.65 18.25 20.95 ;
        RECT 18.55 20.65 18.95 20.95 ;
        RECT 19.9 20.65 20.35 20.95 ;
        RECT 20.65 20.65 21.05 20.95 ;
        RECT 21.3 20.65 22.5 20.95 ;
        RECT 22.75 20.65 23.15 20.95 ;
        RECT 23.45 20.65 23.85 20.95 ;
        RECT 24.85 20.65 25.3 20.95 ;
        RECT 25.6 20.65 26 20.95 ;
        RECT 26.25 20.65 27.45 20.95 ;
        RECT 27.7 20.65 28.1 20.95 ;
        RECT 28.4 20.65 28.8 20.95 ;
        RECT 29.75 20.65 30.2 20.95 ;
        RECT 30.5 20.65 30.9 20.95 ;
        RECT 31.15 20.65 32.35 20.95 ;
        RECT 32.6 20.65 33 20.95 ;
        RECT 33.3 20.65 33.7 20.95 ;
        RECT 34.7 20.65 35.15 20.95 ;
        RECT 35.45 20.65 35.85 20.95 ;
        RECT 36.1 20.65 37.3 20.95 ;
        RECT 37.55 20.65 37.95 20.95 ;
        RECT 38.25 20.65 38.65 20.95 ;
        RECT 2.1 20.05 2.5 20.65 ;
        RECT 7 20.05 7.4 20.65 ;
        RECT 11.9 20.05 12.3 20.65 ;
        RECT 16.8 20.05 17.2 20.65 ;
        RECT 21.7 20.05 22.1 20.65 ;
        RECT 26.65 20.05 27.05 20.65 ;
        RECT 31.55 20.05 31.95 20.65 ;
        RECT 36.5 20.05 36.9 20.65 ;
        RECT 1 19.75 1.4 19.8 ;
        RECT 0.3 19.45 38.65 19.75 ;
        RECT 1 19.4 1.4 19.45 ;
        RECT 2.15 18.8 2.55 19.2 ;
        RECT 7.05 18.8 7.45 19.2 ;
        RECT 11.95 18.8 12.35 19.2 ;
        RECT 16.85 18.8 17.25 19.2 ;
        RECT 21.75 18.8 22.15 19.2 ;
        RECT 26.7 18.8 27.1 19.2 ;
        RECT 31.6 18.8 32 19.2 ;
        RECT 36.55 18.8 36.95 19.2 ;
        RECT 1.1 18.1 1.5 18.8 ;
        RECT 1.75 18.1 2.95 18.8 ;
        RECT 3.2 18.1 3.6 18.8 ;
        RECT 6 18.1 6.4 18.8 ;
        RECT 6.65 18.1 7.85 18.8 ;
        RECT 8.1 18.1 8.5 18.8 ;
        RECT 10.9 18.1 11.3 18.8 ;
        RECT 11.55 18.1 12.75 18.8 ;
        RECT 13 18.1 13.4 18.8 ;
        RECT 15.8 18.1 16.2 18.8 ;
        RECT 16.45 18.1 17.65 18.8 ;
        RECT 17.9 18.1 18.3 18.8 ;
        RECT 20.7 18.1 21.1 18.8 ;
        RECT 21.35 18.1 22.55 18.8 ;
        RECT 22.8 18.1 23.2 18.8 ;
        RECT 25.65 18.1 26.05 18.8 ;
        RECT 26.3 18.1 27.5 18.8 ;
        RECT 27.75 18.1 28.15 18.8 ;
        RECT 30.55 18.1 30.95 18.8 ;
        RECT 31.2 18.1 32.4 18.8 ;
        RECT 32.65 18.1 33.05 18.8 ;
        RECT 35.5 18.1 35.9 18.8 ;
        RECT 36.15 18.1 37.35 18.8 ;
        RECT 37.6 18.1 38 18.8 ;
        RECT 0.45 17.2 1 17.7 ;
        RECT 1.2 17.25 1.4 18.1 ;
        RECT 1.65 17.75 2.05 17.85 ;
        RECT 3.3 17.75 3.5 18.1 ;
        RECT 1.65 17.55 3.5 17.75 ;
        RECT 1.65 17.45 2.05 17.55 ;
        RECT 1.2 17.2 1.5 17.25 ;
        RECT 2.65 17.2 3.05 17.25 ;
        RECT 0.45 16.45 0.65 17.2 ;
        RECT 1.2 16.95 3.05 17.2 ;
        RECT 1.2 16.9 1.5 16.95 ;
        RECT 1.2 16.45 1.4 16.9 ;
        RECT 2.65 16.85 3.05 16.95 ;
        RECT 2.15 16.45 2.55 16.55 ;
        RECT 3.3 16.45 3.5 17.55 ;
        RECT 3.7 16.95 4.2 17.45 ;
        RECT 4 16.45 4.2 16.95 ;
        RECT 5.35 17.2 5.9 17.7 ;
        RECT 6.1 17.25 6.3 18.1 ;
        RECT 6.55 17.75 6.95 17.85 ;
        RECT 8.2 17.75 8.4 18.1 ;
        RECT 6.55 17.55 8.4 17.75 ;
        RECT 6.55 17.45 6.95 17.55 ;
        RECT 6.1 17.2 6.4 17.25 ;
        RECT 7.55 17.2 7.95 17.25 ;
        RECT 5.35 16.45 5.55 17.2 ;
        RECT 6.1 16.95 7.95 17.2 ;
        RECT 6.1 16.9 6.4 16.95 ;
        RECT 6.1 16.45 6.3 16.9 ;
        RECT 7.55 16.85 7.95 16.95 ;
        RECT 7.05 16.45 7.45 16.55 ;
        RECT 8.2 16.45 8.4 17.55 ;
        RECT 8.6 16.95 9.1 17.45 ;
        RECT 8.9 16.45 9.1 16.95 ;
        RECT 10.25 17.2 10.8 17.7 ;
        RECT 11 17.25 11.2 18.1 ;
        RECT 11.45 17.75 11.85 17.85 ;
        RECT 13.1 17.75 13.3 18.1 ;
        RECT 11.45 17.55 13.3 17.75 ;
        RECT 11.45 17.45 11.85 17.55 ;
        RECT 11 17.2 11.3 17.25 ;
        RECT 12.45 17.2 12.85 17.25 ;
        RECT 10.25 16.45 10.45 17.2 ;
        RECT 11 16.95 12.85 17.2 ;
        RECT 11 16.9 11.3 16.95 ;
        RECT 11 16.45 11.2 16.9 ;
        RECT 12.45 16.85 12.85 16.95 ;
        RECT 11.95 16.45 12.35 16.55 ;
        RECT 13.1 16.45 13.3 17.55 ;
        RECT 13.5 16.95 14 17.45 ;
        RECT 13.8 16.45 14 16.95 ;
        RECT 15.15 17.2 15.7 17.7 ;
        RECT 15.9 17.25 16.1 18.1 ;
        RECT 16.35 17.75 16.75 17.85 ;
        RECT 18 17.75 18.2 18.1 ;
        RECT 16.35 17.55 18.2 17.75 ;
        RECT 16.35 17.45 16.75 17.55 ;
        RECT 15.9 17.2 16.2 17.25 ;
        RECT 17.35 17.2 17.75 17.25 ;
        RECT 15.15 16.45 15.35 17.2 ;
        RECT 15.9 16.95 17.75 17.2 ;
        RECT 15.9 16.9 16.2 16.95 ;
        RECT 15.9 16.45 16.1 16.9 ;
        RECT 17.35 16.85 17.75 16.95 ;
        RECT 16.85 16.45 17.25 16.55 ;
        RECT 18 16.45 18.2 17.55 ;
        RECT 18.4 16.95 18.9 17.45 ;
        RECT 18.7 16.45 18.9 16.95 ;
        RECT 20.05 17.2 20.6 17.7 ;
        RECT 20.8 17.25 21 18.1 ;
        RECT 21.25 17.75 21.65 17.85 ;
        RECT 22.9 17.75 23.1 18.1 ;
        RECT 21.25 17.55 23.1 17.75 ;
        RECT 21.25 17.45 21.65 17.55 ;
        RECT 20.8 17.2 21.1 17.25 ;
        RECT 22.25 17.2 22.65 17.25 ;
        RECT 20.05 16.45 20.25 17.2 ;
        RECT 20.8 16.95 22.65 17.2 ;
        RECT 20.8 16.9 21.1 16.95 ;
        RECT 20.8 16.45 21 16.9 ;
        RECT 22.25 16.85 22.65 16.95 ;
        RECT 21.75 16.45 22.15 16.55 ;
        RECT 22.9 16.45 23.1 17.55 ;
        RECT 23.3 16.95 23.8 17.45 ;
        RECT 23.6 16.45 23.8 16.95 ;
        RECT 25 17.2 25.55 17.7 ;
        RECT 25.75 17.25 25.95 18.1 ;
        RECT 26.2 17.75 26.6 17.85 ;
        RECT 27.85 17.75 28.05 18.1 ;
        RECT 26.2 17.55 28.05 17.75 ;
        RECT 26.2 17.45 26.6 17.55 ;
        RECT 25.75 17.2 26.05 17.25 ;
        RECT 27.2 17.2 27.6 17.25 ;
        RECT 25 16.45 25.2 17.2 ;
        RECT 25.75 16.95 27.6 17.2 ;
        RECT 25.75 16.9 26.05 16.95 ;
        RECT 25.75 16.45 25.95 16.9 ;
        RECT 27.2 16.85 27.6 16.95 ;
        RECT 26.7 16.45 27.1 16.55 ;
        RECT 27.85 16.45 28.05 17.55 ;
        RECT 28.25 16.95 28.75 17.45 ;
        RECT 28.55 16.45 28.75 16.95 ;
        RECT 29.9 17.2 30.45 17.7 ;
        RECT 30.65 17.25 30.85 18.1 ;
        RECT 31.1 17.75 31.5 17.85 ;
        RECT 32.75 17.75 32.95 18.1 ;
        RECT 31.1 17.55 32.95 17.75 ;
        RECT 31.1 17.45 31.5 17.55 ;
        RECT 30.65 17.2 30.95 17.25 ;
        RECT 32.1 17.2 32.5 17.25 ;
        RECT 29.9 16.45 30.1 17.2 ;
        RECT 30.65 16.95 32.5 17.2 ;
        RECT 30.65 16.9 30.95 16.95 ;
        RECT 30.65 16.45 30.85 16.9 ;
        RECT 32.1 16.85 32.5 16.95 ;
        RECT 31.6 16.45 32 16.55 ;
        RECT 32.75 16.45 32.95 17.55 ;
        RECT 33.15 16.95 33.65 17.45 ;
        RECT 33.45 16.45 33.65 16.95 ;
        RECT 34.85 17.2 35.4 17.7 ;
        RECT 35.6 17.25 35.8 18.1 ;
        RECT 36.05 17.75 36.45 17.85 ;
        RECT 37.7 17.75 37.9 18.1 ;
        RECT 36.05 17.55 37.9 17.75 ;
        RECT 36.05 17.45 36.45 17.55 ;
        RECT 35.6 17.2 35.9 17.25 ;
        RECT 37.05 17.2 37.45 17.25 ;
        RECT 34.85 16.45 35.05 17.2 ;
        RECT 35.6 16.95 37.45 17.2 ;
        RECT 35.6 16.9 35.9 16.95 ;
        RECT 35.6 16.45 35.8 16.9 ;
        RECT 37.05 16.85 37.45 16.95 ;
        RECT 36.55 16.45 36.95 16.55 ;
        RECT 37.7 16.45 37.9 17.55 ;
        RECT 38.1 16.95 38.6 17.45 ;
        RECT 38.4 16.45 38.6 16.95 ;
        RECT 0.35 16.15 0.8 16.45 ;
        RECT 1.1 16.15 1.5 16.45 ;
        RECT 1.75 16.15 2.95 16.45 ;
        RECT 3.2 16.15 3.6 16.45 ;
        RECT 3.9 16.15 4.3 16.45 ;
        RECT 5.25 16.15 5.7 16.45 ;
        RECT 6 16.15 6.4 16.45 ;
        RECT 6.65 16.15 7.85 16.45 ;
        RECT 8.1 16.15 8.5 16.45 ;
        RECT 8.8 16.15 9.2 16.45 ;
        RECT 10.15 16.15 10.6 16.45 ;
        RECT 10.9 16.15 11.3 16.45 ;
        RECT 11.55 16.15 12.75 16.45 ;
        RECT 13 16.15 13.4 16.45 ;
        RECT 13.7 16.15 14.1 16.45 ;
        RECT 15.05 16.15 15.5 16.45 ;
        RECT 15.8 16.15 16.2 16.45 ;
        RECT 16.45 16.15 17.65 16.45 ;
        RECT 17.9 16.15 18.3 16.45 ;
        RECT 18.6 16.15 19 16.45 ;
        RECT 19.95 16.15 20.4 16.45 ;
        RECT 20.7 16.15 21.1 16.45 ;
        RECT 21.35 16.15 22.55 16.45 ;
        RECT 22.8 16.15 23.2 16.45 ;
        RECT 23.5 16.15 23.9 16.45 ;
        RECT 24.9 16.15 25.35 16.45 ;
        RECT 25.65 16.15 26.05 16.45 ;
        RECT 26.3 16.15 27.5 16.45 ;
        RECT 27.75 16.15 28.15 16.45 ;
        RECT 28.45 16.15 28.85 16.45 ;
        RECT 29.8 16.15 30.25 16.45 ;
        RECT 30.55 16.15 30.95 16.45 ;
        RECT 31.2 16.15 32.4 16.45 ;
        RECT 32.65 16.15 33.05 16.45 ;
        RECT 33.35 16.15 33.75 16.45 ;
        RECT 34.75 16.15 35.2 16.45 ;
        RECT 35.5 16.15 35.9 16.45 ;
        RECT 36.15 16.15 37.35 16.45 ;
        RECT 37.6 16.15 38 16.45 ;
        RECT 38.3 16.15 38.7 16.45 ;
        RECT 2.15 15.55 2.55 16.15 ;
        RECT 7.05 15.55 7.45 16.15 ;
        RECT 11.95 15.55 12.35 16.15 ;
        RECT 16.85 15.55 17.25 16.15 ;
        RECT 21.75 15.55 22.15 16.15 ;
        RECT 26.7 15.55 27.1 16.15 ;
        RECT 31.6 15.55 32 16.15 ;
        RECT 36.55 15.55 36.95 16.15 ;
        RECT 1.05 15.25 1.45 15.3 ;
        RECT 0 14.95 38.7 15.25 ;
        RECT 1.05 14.9 1.45 14.95 ;
        RECT 1.3 13.95 1.6 14.65 ;
        RECT 1.95 14.35 4.05 14.55 ;
        RECT 1.95 13.95 2.2 14.35 ;
        RECT 3.85 13.95 4.05 14.35 ;
        RECT 6.2 13.95 6.5 14.65 ;
        RECT 6.85 14.35 8.95 14.55 ;
        RECT 6.85 13.95 7.1 14.35 ;
        RECT 8.75 13.95 8.95 14.35 ;
        RECT 11.1 13.95 11.4 14.65 ;
        RECT 11.75 14.35 13.85 14.55 ;
        RECT 11.75 13.95 12 14.35 ;
        RECT 13.65 13.95 13.85 14.35 ;
        RECT 16 13.95 16.3 14.65 ;
        RECT 16.65 14.35 18.75 14.55 ;
        RECT 16.65 13.95 16.9 14.35 ;
        RECT 18.55 13.95 18.75 14.35 ;
        RECT 20.9 13.95 21.2 14.65 ;
        RECT 21.55 14.35 23.65 14.55 ;
        RECT 21.55 13.95 21.8 14.35 ;
        RECT 23.45 13.95 23.65 14.35 ;
        RECT 25.85 13.95 26.15 14.65 ;
        RECT 26.5 14.35 28.6 14.55 ;
        RECT 26.5 13.95 26.75 14.35 ;
        RECT 28.4 13.95 28.6 14.35 ;
        RECT 30.75 13.95 31.05 14.65 ;
        RECT 31.4 14.35 33.5 14.55 ;
        RECT 31.4 13.95 31.65 14.35 ;
        RECT 33.3 13.95 33.5 14.35 ;
        RECT 35.7 13.95 36 14.65 ;
        RECT 36.35 14.35 38.45 14.55 ;
        RECT 36.35 13.95 36.6 14.35 ;
        RECT 38.25 13.95 38.45 14.35 ;
        RECT 0.5 13.65 0.95 13.95 ;
        RECT 1.25 13.65 1.65 13.95 ;
        RECT 1.9 13.65 2.3 13.95 ;
        RECT 2.5 13.65 2.9 13.95 ;
        RECT 3.1 13.65 3.5 13.95 ;
        RECT 3.75 13.65 4.15 13.95 ;
        RECT 5.4 13.65 5.85 13.95 ;
        RECT 6.15 13.65 6.55 13.95 ;
        RECT 6.8 13.65 7.2 13.95 ;
        RECT 7.4 13.65 7.8 13.95 ;
        RECT 8 13.65 8.4 13.95 ;
        RECT 8.65 13.65 9.05 13.95 ;
        RECT 10.3 13.65 10.75 13.95 ;
        RECT 11.05 13.65 11.45 13.95 ;
        RECT 11.7 13.65 12.1 13.95 ;
        RECT 12.3 13.65 12.7 13.95 ;
        RECT 12.9 13.65 13.3 13.95 ;
        RECT 13.55 13.65 13.95 13.95 ;
        RECT 15.2 13.65 15.65 13.95 ;
        RECT 15.95 13.65 16.35 13.95 ;
        RECT 16.6 13.65 17 13.95 ;
        RECT 17.2 13.65 17.6 13.95 ;
        RECT 17.8 13.65 18.2 13.95 ;
        RECT 18.45 13.65 18.85 13.95 ;
        RECT 20.1 13.65 20.55 13.95 ;
        RECT 20.85 13.65 21.25 13.95 ;
        RECT 21.5 13.65 21.9 13.95 ;
        RECT 22.1 13.65 22.5 13.95 ;
        RECT 22.7 13.65 23.1 13.95 ;
        RECT 23.35 13.65 23.75 13.95 ;
        RECT 25.05 13.65 25.5 13.95 ;
        RECT 25.8 13.65 26.2 13.95 ;
        RECT 26.45 13.65 26.85 13.95 ;
        RECT 27.05 13.65 27.45 13.95 ;
        RECT 27.65 13.65 28.05 13.95 ;
        RECT 28.3 13.65 28.7 13.95 ;
        RECT 29.95 13.65 30.4 13.95 ;
        RECT 30.7 13.65 31.1 13.95 ;
        RECT 31.35 13.65 31.75 13.95 ;
        RECT 31.95 13.65 32.35 13.95 ;
        RECT 32.55 13.65 32.95 13.95 ;
        RECT 33.2 13.65 33.6 13.95 ;
        RECT 34.9 13.65 35.35 13.95 ;
        RECT 35.65 13.65 36.05 13.95 ;
        RECT 36.3 13.65 36.7 13.95 ;
        RECT 36.9 13.65 37.3 13.95 ;
        RECT 37.5 13.65 37.9 13.95 ;
        RECT 38.15 13.65 38.55 13.95 ;
        RECT 0.6 12.8 0.8 13.65 ;
        RECT 2.55 13.05 2.85 13.65 ;
        RECT 3.2 12.8 3.4 13.65 ;
        RECT 0.6 12.6 3.4 12.8 ;
        RECT 3.85 12.65 4.05 13.65 ;
        RECT 5.5 12.8 5.7 13.65 ;
        RECT 7.45 13.05 7.75 13.65 ;
        RECT 8.1 12.8 8.3 13.65 ;
        RECT 0.6 12.35 0.8 12.6 ;
        RECT 0.45 11.85 0.95 12.35 ;
        RECT 3.7 12.15 4.2 12.65 ;
        RECT 5.5 12.6 8.3 12.8 ;
        RECT 8.75 12.65 8.95 13.65 ;
        RECT 10.4 12.8 10.6 13.65 ;
        RECT 12.35 13.05 12.65 13.65 ;
        RECT 13 12.8 13.2 13.65 ;
        RECT 5.5 12.35 5.7 12.6 ;
        RECT 5.35 11.85 5.85 12.35 ;
        RECT 8.6 12.15 9.1 12.65 ;
        RECT 10.4 12.6 13.2 12.8 ;
        RECT 13.65 12.65 13.85 13.65 ;
        RECT 15.3 12.8 15.5 13.65 ;
        RECT 17.25 13.05 17.55 13.65 ;
        RECT 17.9 12.8 18.1 13.65 ;
        RECT 10.4 12.35 10.6 12.6 ;
        RECT 10.25 11.85 10.75 12.35 ;
        RECT 13.5 12.15 14 12.65 ;
        RECT 15.3 12.6 18.1 12.8 ;
        RECT 18.55 12.65 18.75 13.65 ;
        RECT 20.2 12.8 20.4 13.65 ;
        RECT 22.15 13.05 22.45 13.65 ;
        RECT 22.8 12.8 23 13.65 ;
        RECT 15.3 12.35 15.5 12.6 ;
        RECT 15.15 11.85 15.65 12.35 ;
        RECT 18.4 12.15 18.9 12.65 ;
        RECT 20.2 12.6 23 12.8 ;
        RECT 23.45 12.65 23.65 13.65 ;
        RECT 25.15 12.8 25.35 13.65 ;
        RECT 27.1 13.05 27.4 13.65 ;
        RECT 27.75 12.8 27.95 13.65 ;
        RECT 20.2 12.35 20.4 12.6 ;
        RECT 20.05 11.85 20.55 12.35 ;
        RECT 23.3 12.15 23.8 12.65 ;
        RECT 25.15 12.6 27.95 12.8 ;
        RECT 28.4 12.65 28.6 13.65 ;
        RECT 30.05 12.8 30.25 13.65 ;
        RECT 32 13.05 32.3 13.65 ;
        RECT 32.65 12.8 32.85 13.65 ;
        RECT 25.15 12.35 25.35 12.6 ;
        RECT 25 11.85 25.5 12.35 ;
        RECT 28.25 12.15 28.75 12.65 ;
        RECT 30.05 12.6 32.85 12.8 ;
        RECT 33.3 12.65 33.5 13.65 ;
        RECT 35 12.8 35.2 13.65 ;
        RECT 36.95 13.05 37.25 13.65 ;
        RECT 37.6 12.8 37.8 13.65 ;
        RECT 30.05 12.35 30.25 12.6 ;
        RECT 29.9 11.85 30.4 12.35 ;
        RECT 33.15 12.15 33.65 12.65 ;
        RECT 35 12.6 37.8 12.8 ;
        RECT 38.25 12.65 38.45 13.65 ;
        RECT 35 12.35 35.2 12.6 ;
        RECT 34.85 11.85 35.35 12.35 ;
        RECT 38.1 12.15 38.6 12.65 ;
        RECT 1.9 11.55 2.3 11.6 ;
        RECT 6.8 11.55 7.2 11.6 ;
        RECT 11.7 11.55 12.1 11.6 ;
        RECT 16.6 11.55 17 11.6 ;
        RECT 21.5 11.55 21.9 11.6 ;
        RECT 26.45 11.55 26.85 11.6 ;
        RECT 31.35 11.55 31.75 11.6 ;
        RECT 36.3 11.55 36.7 11.6 ;
        RECT 0 11.25 4.3 11.55 ;
        RECT 4.9 11.25 9.2 11.55 ;
        RECT 9.8 11.25 14.1 11.55 ;
        RECT 14.7 11.25 19 11.55 ;
        RECT 19.6 11.25 23.9 11.55 ;
        RECT 24.55 11.25 28.85 11.55 ;
        RECT 29.45 11.25 33.75 11.55 ;
        RECT 34.4 11.25 38.7 11.55 ;
        RECT 1.9 11.2 2.3 11.25 ;
        RECT 6.8 11.2 7.2 11.25 ;
        RECT 11.7 11.2 12.1 11.25 ;
        RECT 16.6 11.2 17 11.25 ;
        RECT 21.5 11.2 21.9 11.25 ;
        RECT 26.45 11.2 26.85 11.25 ;
        RECT 31.35 11.2 31.75 11.25 ;
        RECT 36.3 11.2 36.7 11.25 ;
        RECT 0.95 10.55 1.25 10.95 ;
        RECT 0.25 8.95 0.65 10.55 ;
        RECT 0.9 8.95 1.3 10.55 ;
        RECT 1.55 8.95 1.95 10.55 ;
        RECT 0.35 8.5 0.55 8.95 ;
        RECT 2.15 8.85 2.45 10.95 ;
        RECT 5.85 10.55 6.15 10.95 ;
        RECT 2.65 8.95 3.05 10.55 ;
        RECT 3.3 8.95 3.7 10.55 ;
        RECT 3.95 8.95 4.35 10.55 ;
        RECT 5.15 8.95 5.55 10.55 ;
        RECT 5.8 8.95 6.2 10.55 ;
        RECT 6.45 8.95 6.85 10.55 ;
        RECT 1.1 8.5 1.5 8.55 ;
        RECT 0.35 8.3 1.5 8.5 ;
        RECT 0.35 7.3 0.55 8.3 ;
        RECT 1.1 8.25 1.5 8.3 ;
        RECT 2.65 8.05 2.85 8.95 ;
        RECT 4.15 8.65 4.35 8.95 ;
        RECT 3.1 8.55 3.5 8.6 ;
        RECT 4.05 8.55 4.45 8.65 ;
        RECT 3.1 8.35 4.45 8.55 ;
        RECT 3.1 8.3 3.5 8.35 ;
        RECT 4.05 8.25 4.45 8.35 ;
        RECT 5.25 8.5 5.45 8.95 ;
        RECT 7.05 8.85 7.35 10.95 ;
        RECT 10.75 10.55 11.05 10.95 ;
        RECT 7.55 8.95 7.95 10.55 ;
        RECT 8.2 8.95 8.6 10.55 ;
        RECT 8.85 8.95 9.25 10.55 ;
        RECT 10.05 8.95 10.45 10.55 ;
        RECT 10.7 8.95 11.1 10.55 ;
        RECT 11.35 8.95 11.75 10.55 ;
        RECT 6 8.5 6.4 8.55 ;
        RECT 5.25 8.3 6.4 8.5 ;
        RECT 2.55 7.95 2.95 8.05 ;
        RECT 3.5 7.95 3.9 8 ;
        RECT 2.55 7.75 3.9 7.95 ;
        RECT 2.55 7.65 2.95 7.75 ;
        RECT 3.5 7.7 3.9 7.75 ;
        RECT 2.65 7.3 2.85 7.65 ;
        RECT 4.15 7.3 4.35 8.25 ;
        RECT 5.25 7.3 5.45 8.3 ;
        RECT 6 8.25 6.4 8.3 ;
        RECT 7.55 8.05 7.75 8.95 ;
        RECT 9.05 8.65 9.25 8.95 ;
        RECT 8 8.55 8.4 8.6 ;
        RECT 8.95 8.55 9.35 8.65 ;
        RECT 8 8.35 9.35 8.55 ;
        RECT 8 8.3 8.4 8.35 ;
        RECT 8.95 8.25 9.35 8.35 ;
        RECT 10.15 8.5 10.35 8.95 ;
        RECT 11.95 8.85 12.25 10.95 ;
        RECT 15.65 10.55 15.95 10.95 ;
        RECT 12.45 8.95 12.85 10.55 ;
        RECT 13.1 8.95 13.5 10.55 ;
        RECT 13.75 8.95 14.15 10.55 ;
        RECT 14.95 8.95 15.35 10.55 ;
        RECT 15.6 8.95 16 10.55 ;
        RECT 16.25 8.95 16.65 10.55 ;
        RECT 10.9 8.5 11.3 8.55 ;
        RECT 10.15 8.3 11.3 8.5 ;
        RECT 7.45 7.95 7.85 8.05 ;
        RECT 8.4 7.95 8.8 8 ;
        RECT 7.45 7.75 8.8 7.95 ;
        RECT 7.45 7.65 7.85 7.75 ;
        RECT 8.4 7.7 8.8 7.75 ;
        RECT 7.55 7.3 7.75 7.65 ;
        RECT 9.05 7.3 9.25 8.25 ;
        RECT 10.15 7.3 10.35 8.3 ;
        RECT 10.9 8.25 11.3 8.3 ;
        RECT 12.45 8.05 12.65 8.95 ;
        RECT 13.95 8.65 14.15 8.95 ;
        RECT 12.9 8.55 13.3 8.6 ;
        RECT 13.85 8.55 14.25 8.65 ;
        RECT 12.9 8.35 14.25 8.55 ;
        RECT 12.9 8.3 13.3 8.35 ;
        RECT 13.85 8.25 14.25 8.35 ;
        RECT 15.05 8.5 15.25 8.95 ;
        RECT 16.85 8.85 17.15 10.95 ;
        RECT 20.55 10.55 20.85 10.95 ;
        RECT 17.35 8.95 17.75 10.55 ;
        RECT 18 8.95 18.4 10.55 ;
        RECT 18.65 8.95 19.05 10.55 ;
        RECT 19.85 8.95 20.25 10.55 ;
        RECT 20.5 8.95 20.9 10.55 ;
        RECT 21.15 8.95 21.55 10.55 ;
        RECT 15.8 8.5 16.2 8.55 ;
        RECT 15.05 8.3 16.2 8.5 ;
        RECT 12.35 7.95 12.75 8.05 ;
        RECT 13.3 7.95 13.7 8 ;
        RECT 12.35 7.75 13.7 7.95 ;
        RECT 12.35 7.65 12.75 7.75 ;
        RECT 13.3 7.7 13.7 7.75 ;
        RECT 12.45 7.3 12.65 7.65 ;
        RECT 13.95 7.3 14.15 8.25 ;
        RECT 15.05 7.3 15.25 8.3 ;
        RECT 15.8 8.25 16.2 8.3 ;
        RECT 17.35 8.05 17.55 8.95 ;
        RECT 18.85 8.65 19.05 8.95 ;
        RECT 17.8 8.55 18.2 8.6 ;
        RECT 18.75 8.55 19.15 8.65 ;
        RECT 17.8 8.35 19.15 8.55 ;
        RECT 17.8 8.3 18.2 8.35 ;
        RECT 18.75 8.25 19.15 8.35 ;
        RECT 19.95 8.5 20.15 8.95 ;
        RECT 21.75 8.85 22.05 10.95 ;
        RECT 25.5 10.55 25.8 10.95 ;
        RECT 22.25 8.95 22.65 10.55 ;
        RECT 22.9 8.95 23.3 10.55 ;
        RECT 23.55 8.95 23.95 10.55 ;
        RECT 24.8 8.95 25.2 10.55 ;
        RECT 25.45 8.95 25.85 10.55 ;
        RECT 26.1 8.95 26.5 10.55 ;
        RECT 20.7 8.5 21.1 8.55 ;
        RECT 19.95 8.3 21.1 8.5 ;
        RECT 17.25 7.95 17.65 8.05 ;
        RECT 18.2 7.95 18.6 8 ;
        RECT 17.25 7.75 18.6 7.95 ;
        RECT 17.25 7.65 17.65 7.75 ;
        RECT 18.2 7.7 18.6 7.75 ;
        RECT 17.35 7.3 17.55 7.65 ;
        RECT 18.85 7.3 19.05 8.25 ;
        RECT 19.95 7.3 20.15 8.3 ;
        RECT 20.7 8.25 21.1 8.3 ;
        RECT 22.25 8.05 22.45 8.95 ;
        RECT 23.75 8.65 23.95 8.95 ;
        RECT 22.7 8.55 23.1 8.6 ;
        RECT 23.65 8.55 24.05 8.65 ;
        RECT 22.7 8.35 24.05 8.55 ;
        RECT 22.7 8.3 23.1 8.35 ;
        RECT 23.65 8.25 24.05 8.35 ;
        RECT 24.9 8.5 25.1 8.95 ;
        RECT 26.7 8.85 27 10.95 ;
        RECT 30.4 10.55 30.7 10.95 ;
        RECT 27.2 8.95 27.6 10.55 ;
        RECT 27.85 8.95 28.25 10.55 ;
        RECT 28.5 8.95 28.9 10.55 ;
        RECT 29.7 8.95 30.1 10.55 ;
        RECT 30.35 8.95 30.75 10.55 ;
        RECT 31 8.95 31.4 10.55 ;
        RECT 25.65 8.5 26.05 8.55 ;
        RECT 24.9 8.3 26.05 8.5 ;
        RECT 22.15 7.95 22.55 8.05 ;
        RECT 23.1 7.95 23.5 8 ;
        RECT 22.15 7.75 23.5 7.95 ;
        RECT 22.15 7.65 22.55 7.75 ;
        RECT 23.1 7.7 23.5 7.75 ;
        RECT 22.25 7.3 22.45 7.65 ;
        RECT 23.75 7.3 23.95 8.25 ;
        RECT 24.9 7.3 25.1 8.3 ;
        RECT 25.65 8.25 26.05 8.3 ;
        RECT 27.2 8.05 27.4 8.95 ;
        RECT 28.7 8.65 28.9 8.95 ;
        RECT 27.65 8.55 28.05 8.6 ;
        RECT 28.6 8.55 29 8.65 ;
        RECT 27.65 8.35 29 8.55 ;
        RECT 27.65 8.3 28.05 8.35 ;
        RECT 28.6 8.25 29 8.35 ;
        RECT 29.8 8.5 30 8.95 ;
        RECT 31.6 8.85 31.9 10.95 ;
        RECT 35.35 10.55 35.65 10.95 ;
        RECT 32.1 8.95 32.5 10.55 ;
        RECT 32.75 8.95 33.15 10.55 ;
        RECT 33.4 8.95 33.8 10.55 ;
        RECT 34.65 8.95 35.05 10.55 ;
        RECT 35.3 8.95 35.7 10.55 ;
        RECT 35.95 8.95 36.35 10.55 ;
        RECT 30.55 8.5 30.95 8.55 ;
        RECT 29.8 8.3 30.95 8.5 ;
        RECT 27.1 7.95 27.5 8.05 ;
        RECT 28.05 7.95 28.45 8 ;
        RECT 27.1 7.75 28.45 7.95 ;
        RECT 27.1 7.65 27.5 7.75 ;
        RECT 28.05 7.7 28.45 7.75 ;
        RECT 27.2 7.3 27.4 7.65 ;
        RECT 28.7 7.3 28.9 8.25 ;
        RECT 29.8 7.3 30 8.3 ;
        RECT 30.55 8.25 30.95 8.3 ;
        RECT 32.1 8.05 32.3 8.95 ;
        RECT 33.6 8.65 33.8 8.95 ;
        RECT 32.55 8.55 32.95 8.6 ;
        RECT 33.5 8.55 33.9 8.65 ;
        RECT 32.55 8.35 33.9 8.55 ;
        RECT 32.55 8.3 32.95 8.35 ;
        RECT 33.5 8.25 33.9 8.35 ;
        RECT 34.75 8.5 34.95 8.95 ;
        RECT 36.55 8.85 36.85 10.95 ;
        RECT 37.05 8.95 37.45 10.55 ;
        RECT 37.7 8.95 38.1 10.55 ;
        RECT 38.35 8.95 38.75 10.55 ;
        RECT 35.5 8.5 35.9 8.55 ;
        RECT 34.75 8.3 35.9 8.5 ;
        RECT 32 7.95 32.4 8.05 ;
        RECT 32.95 7.95 33.35 8 ;
        RECT 32 7.75 33.35 7.95 ;
        RECT 32 7.65 32.4 7.75 ;
        RECT 32.95 7.7 33.35 7.75 ;
        RECT 32.1 7.3 32.3 7.65 ;
        RECT 33.6 7.3 33.8 8.25 ;
        RECT 34.75 7.3 34.95 8.3 ;
        RECT 35.5 8.25 35.9 8.3 ;
        RECT 37.05 8.05 37.25 8.95 ;
        RECT 38.55 8.65 38.75 8.95 ;
        RECT 37.5 8.55 37.9 8.6 ;
        RECT 38.45 8.55 38.85 8.65 ;
        RECT 37.5 8.35 38.85 8.55 ;
        RECT 37.5 8.3 37.9 8.35 ;
        RECT 38.45 8.25 38.85 8.35 ;
        RECT 36.95 7.95 37.35 8.05 ;
        RECT 37.9 7.95 38.3 8 ;
        RECT 36.95 7.75 38.3 7.95 ;
        RECT 36.95 7.65 37.35 7.75 ;
        RECT 37.9 7.7 38.3 7.75 ;
        RECT 37.05 7.3 37.25 7.65 ;
        RECT 38.55 7.3 38.75 8.25 ;
        RECT 0.25 6.4 0.65 7.3 ;
        RECT 0.9 6.4 1.3 7.3 ;
        RECT 1.55 6.4 1.95 7.3 ;
        RECT 0.95 5.95 1.25 6.4 ;
        RECT 2.15 6 2.45 7.3 ;
        RECT 2.65 6.4 3.05 7.3 ;
        RECT 3.3 6.4 3.7 7.3 ;
        RECT 3.95 6.4 4.35 7.3 ;
        RECT 5.15 6.4 5.55 7.3 ;
        RECT 5.8 6.4 6.2 7.3 ;
        RECT 6.45 6.4 6.85 7.3 ;
        RECT 5.85 5.95 6.15 6.4 ;
        RECT 7.05 6 7.35 7.3 ;
        RECT 7.55 6.4 7.95 7.3 ;
        RECT 8.2 6.4 8.6 7.3 ;
        RECT 8.85 6.4 9.25 7.3 ;
        RECT 10.05 6.4 10.45 7.3 ;
        RECT 10.7 6.4 11.1 7.3 ;
        RECT 11.35 6.4 11.75 7.3 ;
        RECT 10.75 5.95 11.05 6.4 ;
        RECT 11.95 6 12.25 7.3 ;
        RECT 12.45 6.4 12.85 7.3 ;
        RECT 13.1 6.4 13.5 7.3 ;
        RECT 13.75 6.4 14.15 7.3 ;
        RECT 14.95 6.4 15.35 7.3 ;
        RECT 15.6 6.4 16 7.3 ;
        RECT 16.25 6.4 16.65 7.3 ;
        RECT 15.65 5.95 15.95 6.4 ;
        RECT 16.85 6 17.15 7.3 ;
        RECT 17.35 6.4 17.75 7.3 ;
        RECT 18 6.4 18.4 7.3 ;
        RECT 18.65 6.4 19.05 7.3 ;
        RECT 19.85 6.4 20.25 7.3 ;
        RECT 20.5 6.4 20.9 7.3 ;
        RECT 21.15 6.4 21.55 7.3 ;
        RECT 20.55 5.95 20.85 6.4 ;
        RECT 21.75 6 22.05 7.3 ;
        RECT 22.25 6.4 22.65 7.3 ;
        RECT 22.9 6.4 23.3 7.3 ;
        RECT 23.55 6.4 23.95 7.3 ;
        RECT 24.8 6.4 25.2 7.3 ;
        RECT 25.45 6.4 25.85 7.3 ;
        RECT 26.1 6.4 26.5 7.3 ;
        RECT 25.5 5.95 25.8 6.4 ;
        RECT 26.7 6 27 7.3 ;
        RECT 27.2 6.4 27.6 7.3 ;
        RECT 27.85 6.4 28.25 7.3 ;
        RECT 28.5 6.4 28.9 7.3 ;
        RECT 29.7 6.4 30.1 7.3 ;
        RECT 30.35 6.4 30.75 7.3 ;
        RECT 31 6.4 31.4 7.3 ;
        RECT 30.4 5.95 30.7 6.4 ;
        RECT 31.6 6 31.9 7.3 ;
        RECT 32.1 6.4 32.5 7.3 ;
        RECT 32.75 6.4 33.15 7.3 ;
        RECT 33.4 6.4 33.8 7.3 ;
        RECT 34.65 6.4 35.05 7.3 ;
        RECT 35.3 6.4 35.7 7.3 ;
        RECT 35.95 6.4 36.35 7.3 ;
        RECT 35.35 5.95 35.65 6.4 ;
        RECT 36.55 6 36.85 7.3 ;
        RECT 37.05 6.4 37.45 7.3 ;
        RECT 37.7 6.4 38.1 7.3 ;
        RECT 38.35 6.4 38.75 7.3 ;
        RECT 0.9 5.65 1.3 5.7 ;
        RECT 5.8 5.65 6.2 5.7 ;
        RECT 10.7 5.65 11.1 5.7 ;
        RECT 15.6 5.65 16 5.7 ;
        RECT 20.5 5.65 20.9 5.7 ;
        RECT 25.45 5.65 25.85 5.7 ;
        RECT 30.35 5.65 30.75 5.7 ;
        RECT 35.3 5.65 35.7 5.7 ;
        RECT 0 5.35 4.6 5.65 ;
        RECT 4.9 5.35 9.5 5.65 ;
        RECT 9.8 5.35 14.4 5.65 ;
        RECT 14.7 5.35 19.3 5.65 ;
        RECT 19.6 5.35 24.2 5.65 ;
        RECT 24.55 5.35 29.15 5.65 ;
        RECT 29.45 5.35 34.05 5.65 ;
        RECT 34.4 5.35 39 5.65 ;
        RECT 0.9 5.3 1.3 5.35 ;
        RECT 5.8 5.3 6.2 5.35 ;
        RECT 10.7 5.3 11.1 5.35 ;
        RECT 15.6 5.3 16 5.35 ;
        RECT 20.5 5.3 20.9 5.35 ;
        RECT 25.45 5.3 25.85 5.35 ;
        RECT 30.35 5.3 30.75 5.35 ;
        RECT 35.3 5.3 35.7 5.35 ;
        RECT 2.45 4.65 2.75 5.05 ;
        RECT 7.35 4.65 7.65 5.05 ;
        RECT 12.25 4.65 12.55 5.05 ;
        RECT 17.15 4.65 17.45 5.05 ;
        RECT 22.05 4.65 22.35 5.05 ;
        RECT 27 4.65 27.3 5.05 ;
        RECT 31.9 4.65 32.2 5.05 ;
        RECT 36.85 4.65 37.15 5.05 ;
        RECT 1.2 3.95 1.6 4.65 ;
        RECT 1.85 3.95 2.25 4.65 ;
        RECT 2.45 3.95 3.35 4.65 ;
        RECT 3.6 3.95 4 4.65 ;
        RECT 6.1 3.95 6.5 4.65 ;
        RECT 6.75 3.95 7.15 4.65 ;
        RECT 7.35 3.95 8.25 4.65 ;
        RECT 8.5 3.95 8.9 4.65 ;
        RECT 11 3.95 11.4 4.65 ;
        RECT 11.65 3.95 12.05 4.65 ;
        RECT 12.25 3.95 13.15 4.65 ;
        RECT 13.4 3.95 13.8 4.65 ;
        RECT 15.9 3.95 16.3 4.65 ;
        RECT 16.55 3.95 16.95 4.65 ;
        RECT 17.15 3.95 18.05 4.65 ;
        RECT 18.3 3.95 18.7 4.65 ;
        RECT 20.8 3.95 21.2 4.65 ;
        RECT 21.45 3.95 21.85 4.65 ;
        RECT 22.05 3.95 22.95 4.65 ;
        RECT 23.2 3.95 23.6 4.65 ;
        RECT 25.75 3.95 26.15 4.65 ;
        RECT 26.4 3.95 26.8 4.65 ;
        RECT 27 3.95 27.9 4.65 ;
        RECT 28.15 3.95 28.55 4.65 ;
        RECT 30.65 3.95 31.05 4.65 ;
        RECT 31.3 3.95 31.7 4.65 ;
        RECT 31.9 3.95 32.8 4.65 ;
        RECT 33.05 3.95 33.45 4.65 ;
        RECT 35.6 3.95 36 4.65 ;
        RECT 36.25 3.95 36.65 4.65 ;
        RECT 36.85 3.95 37.75 4.65 ;
        RECT 38 3.95 38.4 4.65 ;
        RECT 0.55 3.7 0.95 3.8 ;
        RECT 1.3 3.7 1.5 3.95 ;
        RECT 2.45 3.9 2.75 3.95 ;
        RECT 0.55 3.5 1.5 3.7 ;
        RECT 3.7 3.7 3.9 3.95 ;
        RECT 5.45 3.7 5.85 3.8 ;
        RECT 6.2 3.7 6.4 3.95 ;
        RECT 7.35 3.9 7.65 3.95 ;
        RECT 0.55 3.4 0.95 3.5 ;
        RECT 0.55 2.8 0.95 3.2 ;
        RECT 0.65 2.6 0.85 2.8 ;
        RECT 1.3 2.6 1.5 3.5 ;
        RECT 1.7 3.55 2.1 3.6 ;
        RECT 3.7 3.55 4.15 3.7 ;
        RECT 1.7 3.35 4.15 3.55 ;
        RECT 5.45 3.5 6.4 3.7 ;
        RECT 8.6 3.7 8.8 3.95 ;
        RECT 10.35 3.7 10.75 3.8 ;
        RECT 11.1 3.7 11.3 3.95 ;
        RECT 12.25 3.9 12.55 3.95 ;
        RECT 5.45 3.4 5.85 3.5 ;
        RECT 1.7 3.3 2.1 3.35 ;
        RECT 3.7 3.25 4.15 3.35 ;
        RECT 3.7 2.6 3.9 3.25 ;
        RECT 5.45 2.8 5.85 3.2 ;
        RECT 5.55 2.6 5.75 2.8 ;
        RECT 6.2 2.6 6.4 3.5 ;
        RECT 6.6 3.55 7 3.6 ;
        RECT 8.6 3.55 9.05 3.7 ;
        RECT 6.6 3.35 9.05 3.55 ;
        RECT 10.35 3.5 11.3 3.7 ;
        RECT 13.5 3.7 13.7 3.95 ;
        RECT 15.25 3.7 15.65 3.8 ;
        RECT 16 3.7 16.2 3.95 ;
        RECT 17.15 3.9 17.45 3.95 ;
        RECT 10.35 3.4 10.75 3.5 ;
        RECT 6.6 3.3 7 3.35 ;
        RECT 8.6 3.25 9.05 3.35 ;
        RECT 8.6 2.6 8.8 3.25 ;
        RECT 10.35 2.8 10.75 3.2 ;
        RECT 10.45 2.6 10.65 2.8 ;
        RECT 11.1 2.6 11.3 3.5 ;
        RECT 11.5 3.55 11.9 3.6 ;
        RECT 13.5 3.55 13.95 3.7 ;
        RECT 11.5 3.35 13.95 3.55 ;
        RECT 15.25 3.5 16.2 3.7 ;
        RECT 18.4 3.7 18.6 3.95 ;
        RECT 20.15 3.7 20.55 3.8 ;
        RECT 20.9 3.7 21.1 3.95 ;
        RECT 22.05 3.9 22.35 3.95 ;
        RECT 15.25 3.4 15.65 3.5 ;
        RECT 11.5 3.3 11.9 3.35 ;
        RECT 13.5 3.25 13.95 3.35 ;
        RECT 13.5 2.6 13.7 3.25 ;
        RECT 15.25 2.8 15.65 3.2 ;
        RECT 15.35 2.6 15.55 2.8 ;
        RECT 16 2.6 16.2 3.5 ;
        RECT 16.4 3.55 16.8 3.6 ;
        RECT 18.4 3.55 18.85 3.7 ;
        RECT 16.4 3.35 18.85 3.55 ;
        RECT 20.15 3.5 21.1 3.7 ;
        RECT 23.3 3.7 23.5 3.95 ;
        RECT 25.1 3.7 25.5 3.8 ;
        RECT 25.85 3.7 26.05 3.95 ;
        RECT 27 3.9 27.3 3.95 ;
        RECT 20.15 3.4 20.55 3.5 ;
        RECT 16.4 3.3 16.8 3.35 ;
        RECT 18.4 3.25 18.85 3.35 ;
        RECT 18.4 2.6 18.6 3.25 ;
        RECT 20.15 2.8 20.55 3.2 ;
        RECT 20.25 2.6 20.45 2.8 ;
        RECT 20.9 2.6 21.1 3.5 ;
        RECT 21.3 3.55 21.7 3.6 ;
        RECT 23.3 3.55 23.75 3.7 ;
        RECT 21.3 3.35 23.75 3.55 ;
        RECT 25.1 3.5 26.05 3.7 ;
        RECT 28.25 3.7 28.45 3.95 ;
        RECT 30 3.7 30.4 3.8 ;
        RECT 30.75 3.7 30.95 3.95 ;
        RECT 31.9 3.9 32.2 3.95 ;
        RECT 25.1 3.4 25.5 3.5 ;
        RECT 21.3 3.3 21.7 3.35 ;
        RECT 23.3 3.25 23.75 3.35 ;
        RECT 23.3 2.6 23.5 3.25 ;
        RECT 25.1 2.8 25.5 3.2 ;
        RECT 25.2 2.6 25.4 2.8 ;
        RECT 25.85 2.6 26.05 3.5 ;
        RECT 26.25 3.55 26.65 3.6 ;
        RECT 28.25 3.55 28.7 3.7 ;
        RECT 26.25 3.35 28.7 3.55 ;
        RECT 30 3.5 30.95 3.7 ;
        RECT 33.15 3.7 33.35 3.95 ;
        RECT 34.95 3.7 35.35 3.8 ;
        RECT 35.7 3.7 35.9 3.95 ;
        RECT 36.85 3.9 37.15 3.95 ;
        RECT 30 3.4 30.4 3.5 ;
        RECT 26.25 3.3 26.65 3.35 ;
        RECT 28.25 3.25 28.7 3.35 ;
        RECT 28.25 2.6 28.45 3.25 ;
        RECT 30 2.8 30.4 3.2 ;
        RECT 30.1 2.6 30.3 2.8 ;
        RECT 30.75 2.6 30.95 3.5 ;
        RECT 31.15 3.55 31.55 3.6 ;
        RECT 33.15 3.55 33.6 3.7 ;
        RECT 31.15 3.35 33.6 3.55 ;
        RECT 34.95 3.5 35.9 3.7 ;
        RECT 38.1 3.7 38.3 3.95 ;
        RECT 34.95 3.4 35.35 3.5 ;
        RECT 31.15 3.3 31.55 3.35 ;
        RECT 33.15 3.25 33.6 3.35 ;
        RECT 33.15 2.6 33.35 3.25 ;
        RECT 34.95 2.8 35.35 3.2 ;
        RECT 35.05 2.6 35.25 2.8 ;
        RECT 35.7 2.6 35.9 3.5 ;
        RECT 36.1 3.55 36.5 3.6 ;
        RECT 38.1 3.55 38.55 3.7 ;
        RECT 36.1 3.35 38.55 3.55 ;
        RECT 36.1 3.3 36.5 3.35 ;
        RECT 38.1 3.25 38.55 3.35 ;
        RECT 38.1 2.6 38.3 3.25 ;
        RECT 0.55 1.7 0.95 2.6 ;
        RECT 1.2 1.7 1.6 2.6 ;
        RECT 1.85 1.7 2.25 2.6 ;
        RECT 2.45 1.7 3.35 2.6 ;
        RECT 3.6 1.7 4 2.6 ;
        RECT 5.45 1.7 5.85 2.6 ;
        RECT 6.1 1.7 6.5 2.6 ;
        RECT 6.75 1.7 7.15 2.6 ;
        RECT 7.35 1.7 8.25 2.6 ;
        RECT 8.5 1.7 8.9 2.6 ;
        RECT 10.35 1.7 10.75 2.6 ;
        RECT 11 1.7 11.4 2.6 ;
        RECT 11.65 1.7 12.05 2.6 ;
        RECT 12.25 1.7 13.15 2.6 ;
        RECT 13.4 1.7 13.8 2.6 ;
        RECT 15.25 1.7 15.65 2.6 ;
        RECT 15.9 1.7 16.3 2.6 ;
        RECT 16.55 1.7 16.95 2.6 ;
        RECT 17.15 1.7 18.05 2.6 ;
        RECT 18.3 1.7 18.7 2.6 ;
        RECT 20.15 1.7 20.55 2.6 ;
        RECT 20.8 1.7 21.2 2.6 ;
        RECT 21.45 1.7 21.85 2.6 ;
        RECT 22.05 1.7 22.95 2.6 ;
        RECT 23.2 1.7 23.6 2.6 ;
        RECT 25.1 1.7 25.5 2.6 ;
        RECT 25.75 1.7 26.15 2.6 ;
        RECT 26.4 1.7 26.8 2.6 ;
        RECT 27 1.7 27.9 2.6 ;
        RECT 28.15 1.7 28.55 2.6 ;
        RECT 30 1.7 30.4 2.6 ;
        RECT 30.65 1.7 31.05 2.6 ;
        RECT 31.3 1.7 31.7 2.6 ;
        RECT 31.9 1.7 32.8 2.6 ;
        RECT 33.05 1.7 33.45 2.6 ;
        RECT 34.95 1.7 35.35 2.6 ;
        RECT 35.6 1.7 36 2.6 ;
        RECT 36.25 1.7 36.65 2.6 ;
        RECT 36.85 1.7 37.75 2.6 ;
        RECT 38 1.7 38.4 2.6 ;
        RECT 2.45 1.3 2.75 1.7 ;
        RECT 7.35 1.3 7.65 1.7 ;
        RECT 12.25 1.3 12.55 1.7 ;
        RECT 17.15 1.3 17.45 1.7 ;
        RECT 22.05 1.3 22.35 1.7 ;
        RECT 27 1.3 27.3 1.7 ;
        RECT 31.9 1.3 32.2 1.7 ;
        RECT 36.85 1.3 37.15 1.7 ;
        RECT 1.2 0.95 1.55 1 ;
        RECT 6.1 0.95 6.45 1 ;
        RECT 11 0.95 11.35 1 ;
        RECT 15.9 0.95 16.25 1 ;
        RECT 20.8 0.95 21.15 1 ;
        RECT 25.75 0.95 26.1 1 ;
        RECT 30.65 0.95 31 1 ;
        RECT 35.6 0.95 35.95 1 ;
        RECT 0.45 0.65 4.25 0.95 ;
        RECT 5.35 0.65 9.15 0.95 ;
        RECT 10.25 0.65 14.05 0.95 ;
        RECT 15.15 0.65 18.95 0.95 ;
        RECT 20.05 0.65 23.85 0.95 ;
        RECT 25 0.65 28.8 0.95 ;
        RECT 29.9 0.65 33.7 0.95 ;
        RECT 34.85 0.65 38.65 0.95 ;
        RECT 1.2 0.6 1.55 0.65 ;
        RECT 6.1 0.6 6.45 0.65 ;
        RECT 11 0.6 11.35 0.65 ;
        RECT 15.9 0.6 16.25 0.65 ;
        RECT 20.8 0.6 21.15 0.65 ;
        RECT 25.75 0.6 26.1 0.65 ;
        RECT 30.65 0.6 31 0.65 ;
        RECT 35.6 0.6 35.95 0.65 ;
        RECT 1.85 0.35 2.2 0.4 ;
        RECT 6.75 0.35 7.1 0.4 ;
        RECT 11.65 0.35 12 0.4 ;
        RECT 16.55 0.35 16.9 0.4 ;
        RECT 21.45 0.35 21.8 0.4 ;
        RECT 26.4 0.35 26.75 0.4 ;
        RECT 31.3 0.35 31.65 0.4 ;
        RECT 36.25 0.35 36.6 0.4 ;
        RECT 0.45 0.05 4.25 0.35 ;
        RECT 5.35 0.05 9.15 0.35 ;
        RECT 10.25 0.05 14.05 0.35 ;
        RECT 15.15 0.05 18.95 0.35 ;
        RECT 20.05 0.05 23.85 0.35 ;
        RECT 25 0.05 28.8 0.35 ;
        RECT 29.9 0.05 33.7 0.35 ;
        RECT 34.85 0.05 38.65 0.35 ;
        RECT 1.85 0 2.2 0.05 ;
        RECT 6.75 0 7.1 0.05 ;
        RECT 11.65 0 12 0.05 ;
        RECT 16.55 0 16.9 0.05 ;
        RECT 21.45 0 21.8 0.05 ;
        RECT 26.4 0 26.75 0.05 ;
        RECT 31.3 0 31.65 0.05 ;
        RECT 36.25 0 36.6 0.05 ;
      LAYER met1 ;
        RECT 0 32.6 38.65 32.9 ;
        RECT 0 32.5 0.4 32.6 ;
        RECT 0.4 30.9 0.95 31.4 ;
        RECT 3.65 30.65 4.15 31.15 ;
        RECT 5.3 30.9 5.85 31.4 ;
        RECT 8.55 30.65 9.05 31.15 ;
        RECT 10.2 30.9 10.75 31.4 ;
        RECT 13.45 30.65 13.95 31.15 ;
        RECT 15.1 30.9 15.65 31.4 ;
        RECT 18.35 30.65 18.85 31.15 ;
        RECT 20 30.9 20.55 31.4 ;
        RECT 23.25 30.65 23.75 31.15 ;
        RECT 24.95 30.9 25.5 31.4 ;
        RECT 28.2 30.65 28.7 31.15 ;
        RECT 29.85 30.9 30.4 31.4 ;
        RECT 33.1 30.65 33.6 31.15 ;
        RECT 34.8 30.9 35.35 31.4 ;
        RECT 38.05 30.65 38.55 31.15 ;
        RECT 3.15 29.55 3.55 29.6 ;
        RECT 0.3 29.25 38.65 29.55 ;
        RECT 3.15 29.2 3.55 29.25 ;
        RECT 0 28 38.65 28.3 ;
        RECT 0 27.9 0.4 28 ;
        RECT 0.4 26.3 0.95 26.8 ;
        RECT 3.65 26.05 4.15 26.55 ;
        RECT 5.3 26.3 5.85 26.8 ;
        RECT 8.55 26.05 9.05 26.55 ;
        RECT 10.2 26.3 10.75 26.8 ;
        RECT 13.45 26.05 13.95 26.55 ;
        RECT 15.1 26.3 15.65 26.8 ;
        RECT 18.35 26.05 18.85 26.55 ;
        RECT 20 26.3 20.55 26.8 ;
        RECT 23.25 26.05 23.75 26.55 ;
        RECT 24.95 26.3 25.5 26.8 ;
        RECT 28.2 26.05 28.7 26.55 ;
        RECT 29.85 26.3 30.4 26.8 ;
        RECT 33.1 26.05 33.6 26.55 ;
        RECT 34.8 26.3 35.35 26.8 ;
        RECT 38.05 26.05 38.55 26.55 ;
        RECT 3.15 24.95 3.55 25 ;
        RECT 0.3 24.65 38.65 24.95 ;
        RECT 3.15 24.6 3.55 24.65 ;
        RECT 0 23.4 38.65 23.7 ;
        RECT 0 23.3 0.4 23.4 ;
        RECT 0.4 21.7 0.95 22.2 ;
        RECT 3.65 21.45 4.15 21.95 ;
        RECT 5.3 21.7 5.85 22.2 ;
        RECT 8.55 21.45 9.05 21.95 ;
        RECT 10.2 21.7 10.75 22.2 ;
        RECT 13.45 21.45 13.95 21.95 ;
        RECT 15.1 21.7 15.65 22.2 ;
        RECT 18.35 21.45 18.85 21.95 ;
        RECT 20 21.7 20.55 22.2 ;
        RECT 23.25 21.45 23.75 21.95 ;
        RECT 24.95 21.7 25.5 22.2 ;
        RECT 28.2 21.45 28.7 21.95 ;
        RECT 29.85 21.7 30.4 22.2 ;
        RECT 33.1 21.45 33.6 21.95 ;
        RECT 34.8 21.7 35.35 22.2 ;
        RECT 38.05 21.45 38.55 21.95 ;
        RECT 3.15 20.35 3.55 20.4 ;
        RECT 0.3 20.05 38.65 20.35 ;
        RECT 3.15 20 3.55 20.05 ;
        RECT 0 18.9 38.7 19.2 ;
        RECT 0 18.8 0.4 18.9 ;
        RECT 4.9 18.8 5.3 18.9 ;
        RECT 9.8 18.8 10.2 18.9 ;
        RECT 14.7 18.8 15.1 18.9 ;
        RECT 19.6 18.8 20 18.9 ;
        RECT 24.55 18.8 24.95 18.9 ;
        RECT 29.45 18.8 29.85 18.9 ;
        RECT 34.4 18.8 34.8 18.9 ;
        RECT 0.45 17.2 1 17.7 ;
        RECT 3.7 16.95 4.2 17.45 ;
        RECT 5.35 17.2 5.9 17.7 ;
        RECT 8.6 16.95 9.1 17.45 ;
        RECT 10.25 17.2 10.8 17.7 ;
        RECT 13.5 16.95 14 17.45 ;
        RECT 15.15 17.2 15.7 17.7 ;
        RECT 18.4 16.95 18.9 17.45 ;
        RECT 20.05 17.2 20.6 17.7 ;
        RECT 23.3 16.95 23.8 17.45 ;
        RECT 25 17.2 25.55 17.7 ;
        RECT 28.25 16.95 28.75 17.45 ;
        RECT 29.9 17.2 30.45 17.7 ;
        RECT 33.15 16.95 33.65 17.45 ;
        RECT 34.85 17.2 35.4 17.7 ;
        RECT 38.1 16.95 38.6 17.45 ;
        RECT 3.15 15.85 3.55 15.9 ;
        RECT 8.05 15.85 8.45 15.9 ;
        RECT 12.95 15.85 13.35 15.9 ;
        RECT 17.85 15.85 18.25 15.9 ;
        RECT 22.75 15.85 23.15 15.9 ;
        RECT 27.7 15.85 28.1 15.9 ;
        RECT 32.6 15.85 33 15.9 ;
        RECT 37.55 15.85 37.95 15.9 ;
        RECT 0 15.55 38.7 15.85 ;
        RECT 3.15 15.5 3.55 15.55 ;
        RECT 8.05 15.5 8.45 15.55 ;
        RECT 12.95 15.5 13.35 15.55 ;
        RECT 17.85 15.5 18.25 15.55 ;
        RECT 22.75 15.5 23.15 15.55 ;
        RECT 27.7 15.5 28.1 15.55 ;
        RECT 32.6 15.5 33 15.55 ;
        RECT 37.55 15.5 37.95 15.55 ;
        RECT 0 14.35 38.7 14.65 ;
        RECT 1.3 13.9 1.6 14.35 ;
        RECT 6.2 13.9 6.5 14.35 ;
        RECT 11.1 13.9 11.4 14.35 ;
        RECT 16 13.9 16.3 14.35 ;
        RECT 20.9 13.9 21.2 14.35 ;
        RECT 25.85 13.9 26.15 14.35 ;
        RECT 30.75 13.9 31.05 14.35 ;
        RECT 35.7 13.9 36 14.35 ;
        RECT 3.15 13.35 3.55 13.4 ;
        RECT 8.05 13.35 8.45 13.4 ;
        RECT 12.95 13.35 13.35 13.4 ;
        RECT 17.85 13.35 18.25 13.4 ;
        RECT 22.75 13.35 23.15 13.4 ;
        RECT 27.7 13.35 28.1 13.4 ;
        RECT 32.6 13.35 33 13.4 ;
        RECT 37.55 13.35 37.95 13.4 ;
        RECT 0 13.05 9.2 13.35 ;
        RECT 9.8 13.05 38.7 13.35 ;
        RECT 3.15 13 3.55 13.05 ;
        RECT 8.05 13 8.45 13.05 ;
        RECT 12.95 13 13.35 13.05 ;
        RECT 17.85 13 18.25 13.05 ;
        RECT 22.75 13 23.15 13.05 ;
        RECT 27.7 13 28.1 13.05 ;
        RECT 32.6 13 33 13.05 ;
        RECT 37.55 13 37.95 13.05 ;
        RECT 0.45 11.85 0.95 12.35 ;
        RECT 3.7 12.15 4.2 12.65 ;
        RECT 5.35 11.85 5.85 12.35 ;
        RECT 8.6 12.15 9.1 12.65 ;
        RECT 10.25 11.85 10.75 12.35 ;
        RECT 13.5 12.15 14 12.65 ;
        RECT 15.15 11.85 15.65 12.35 ;
        RECT 18.4 12.15 18.9 12.65 ;
        RECT 20.05 11.85 20.55 12.35 ;
        RECT 23.3 12.15 23.8 12.65 ;
        RECT 25 11.85 25.5 12.35 ;
        RECT 28.25 12.15 28.75 12.65 ;
        RECT 29.9 11.85 30.4 12.35 ;
        RECT 33.15 12.15 33.65 12.65 ;
        RECT 34.85 11.85 35.35 12.35 ;
        RECT 38.1 12.15 38.6 12.65 ;
        RECT 0 10.95 0.4 11 ;
        RECT 4.9 10.95 5.3 11 ;
        RECT 9.8 10.95 10.2 11 ;
        RECT 14.7 10.95 15.1 11 ;
        RECT 19.6 10.95 20 11 ;
        RECT 24.55 10.95 24.95 11 ;
        RECT 29.45 10.95 29.85 11 ;
        RECT 34.4 10.95 34.8 11 ;
        RECT 0 10.65 39 10.95 ;
        RECT 0 10.6 0.4 10.65 ;
        RECT 4.6 10.6 5.3 10.65 ;
        RECT 9.8 10.6 10.2 10.65 ;
        RECT 14.7 10.6 15.1 10.65 ;
        RECT 19.6 10.6 20 10.65 ;
        RECT 24.55 10.6 24.95 10.65 ;
        RECT 29.45 10.6 29.85 10.65 ;
        RECT 34.4 10.6 34.8 10.65 ;
        RECT 1.55 9.6 3.7 9.9 ;
        RECT 6.45 9.6 8.6 9.9 ;
        RECT 11.35 9.6 13.5 9.9 ;
        RECT 16.25 9.6 18.4 9.9 ;
        RECT 21.15 9.6 23.3 9.9 ;
        RECT 26.1 9.6 28.25 9.9 ;
        RECT 31 9.6 33.15 9.9 ;
        RECT 35.95 9.6 38.1 9.9 ;
        RECT 4.05 8.25 4.45 8.65 ;
        RECT 8.95 8.25 9.35 8.65 ;
        RECT 13.85 8.25 14.25 8.65 ;
        RECT 18.75 8.25 19.15 8.65 ;
        RECT 23.65 8.25 24.05 8.65 ;
        RECT 28.6 8.25 29 8.65 ;
        RECT 33.5 8.25 33.9 8.65 ;
        RECT 38.45 8.25 38.85 8.65 ;
        RECT 2.55 7.65 2.95 8.05 ;
        RECT 7.45 7.65 7.85 8.05 ;
        RECT 12.35 7.65 12.75 8.05 ;
        RECT 17.25 7.65 17.65 8.05 ;
        RECT 22.15 7.65 22.55 8.05 ;
        RECT 27.1 7.65 27.5 8.05 ;
        RECT 32 7.65 32.4 8.05 ;
        RECT 36.95 7.65 37.35 8.05 ;
        RECT 1.55 6.7 3.7 7 ;
        RECT 6.45 6.7 8.6 7 ;
        RECT 11.35 6.7 13.5 7 ;
        RECT 16.25 6.7 18.4 7 ;
        RECT 21.15 6.7 23.3 7 ;
        RECT 26.1 6.7 28.25 7 ;
        RECT 31 6.7 33.15 7 ;
        RECT 35.95 6.7 38.1 7 ;
        RECT 3.15 6.25 3.55 6.3 ;
        RECT 8.05 6.25 8.45 6.3 ;
        RECT 12.95 6.25 13.35 6.3 ;
        RECT 17.85 6.25 18.25 6.3 ;
        RECT 22.75 6.25 23.15 6.3 ;
        RECT 27.7 6.25 28.1 6.3 ;
        RECT 32.6 6.25 33 6.3 ;
        RECT 37.55 6.25 37.95 6.3 ;
        RECT 0 5.95 39 6.25 ;
        RECT 3.15 5.9 3.55 5.95 ;
        RECT 8.05 5.9 8.45 5.95 ;
        RECT 12.95 5.9 13.35 5.95 ;
        RECT 17.85 5.9 18.25 5.95 ;
        RECT 22.75 5.9 23.15 5.95 ;
        RECT 27.7 5.9 28.1 5.95 ;
        RECT 32.6 5.9 33 5.95 ;
        RECT 37.55 5.9 37.95 5.95 ;
        RECT 0 5.05 0.4 5.1 ;
        RECT 4.9 5.05 5.3 5.1 ;
        RECT 9.8 5.05 10.2 5.1 ;
        RECT 14.7 5.05 15.1 5.1 ;
        RECT 19.6 5.05 20 5.1 ;
        RECT 24.55 5.05 24.95 5.1 ;
        RECT 29.45 5.05 29.85 5.1 ;
        RECT 34.4 5.05 34.8 5.1 ;
        RECT 0 4.75 38.65 5.05 ;
        RECT 0 4.7 0.4 4.75 ;
        RECT 4.9 4.7 5.3 4.75 ;
        RECT 9.8 4.7 10.2 4.75 ;
        RECT 14.7 4.7 15.1 4.75 ;
        RECT 19.6 4.7 20 4.75 ;
        RECT 24.55 4.7 24.95 4.75 ;
        RECT 29.45 4.7 29.85 4.75 ;
        RECT 34.4 4.7 34.8 4.75 ;
        RECT 1.85 4.15 2.25 4.45 ;
        RECT 6.75 4.15 7.15 4.45 ;
        RECT 11.65 4.15 12.05 4.45 ;
        RECT 16.55 4.15 16.95 4.45 ;
        RECT 21.45 4.15 21.85 4.45 ;
        RECT 26.4 4.15 26.8 4.45 ;
        RECT 31.3 4.15 31.7 4.45 ;
        RECT 36.25 4.15 36.65 4.45 ;
        RECT 0.55 3.4 0.95 3.8 ;
        RECT 1.9 3.6 2.2 4.15 ;
        RECT 1.9 3.35 3.7 3.6 ;
        RECT 0.55 2.8 0.95 3.2 ;
        RECT 1.9 2.3 2.2 3.35 ;
        RECT 3.75 3.3 4.1 3.65 ;
        RECT 5.45 3.4 5.85 3.8 ;
        RECT 6.8 3.6 7.1 4.15 ;
        RECT 6.8 3.35 8.6 3.6 ;
        RECT 5.45 2.8 5.85 3.2 ;
        RECT 6.8 2.3 7.1 3.35 ;
        RECT 8.65 3.3 9 3.65 ;
        RECT 10.35 3.4 10.75 3.8 ;
        RECT 11.7 3.6 12 4.15 ;
        RECT 11.7 3.35 13.5 3.6 ;
        RECT 10.35 2.8 10.75 3.2 ;
        RECT 11.7 2.3 12 3.35 ;
        RECT 13.55 3.3 13.9 3.65 ;
        RECT 15.25 3.4 15.65 3.8 ;
        RECT 16.6 3.6 16.9 4.15 ;
        RECT 16.6 3.35 18.4 3.6 ;
        RECT 15.25 2.8 15.65 3.2 ;
        RECT 16.6 2.3 16.9 3.35 ;
        RECT 18.45 3.3 18.8 3.65 ;
        RECT 20.15 3.4 20.55 3.8 ;
        RECT 21.5 3.6 21.8 4.15 ;
        RECT 21.5 3.35 23.3 3.6 ;
        RECT 20.15 2.8 20.55 3.2 ;
        RECT 21.5 2.3 21.8 3.35 ;
        RECT 23.35 3.3 23.7 3.65 ;
        RECT 25.1 3.4 25.5 3.8 ;
        RECT 26.45 3.6 26.75 4.15 ;
        RECT 26.45 3.35 28.25 3.6 ;
        RECT 25.1 2.8 25.5 3.2 ;
        RECT 26.45 2.3 26.75 3.35 ;
        RECT 28.3 3.3 28.65 3.65 ;
        RECT 30 3.4 30.4 3.8 ;
        RECT 31.35 3.6 31.65 4.15 ;
        RECT 31.35 3.35 33.15 3.6 ;
        RECT 30 2.8 30.4 3.2 ;
        RECT 31.35 2.3 31.65 3.35 ;
        RECT 33.2 3.3 33.55 3.65 ;
        RECT 34.95 3.4 35.35 3.8 ;
        RECT 36.3 3.6 36.6 4.15 ;
        RECT 36.3 3.35 38.1 3.6 ;
        RECT 34.95 2.8 35.35 3.2 ;
        RECT 36.3 2.3 36.6 3.35 ;
        RECT 38.15 3.3 38.5 3.65 ;
        RECT 1.85 2 2.25 2.3 ;
        RECT 6.75 2 7.15 2.3 ;
        RECT 11.65 2 12.05 2.3 ;
        RECT 16.55 2 16.95 2.3 ;
        RECT 21.45 2 21.85 2.3 ;
        RECT 26.4 2 26.8 2.3 ;
        RECT 31.3 2 31.7 2.3 ;
        RECT 36.25 2 36.65 2.3 ;
        RECT 3.15 1.55 3.55 1.6 ;
        RECT 8.05 1.55 8.45 1.6 ;
        RECT 12.95 1.55 13.35 1.6 ;
        RECT 17.85 1.55 18.25 1.6 ;
        RECT 22.75 1.55 23.15 1.6 ;
        RECT 27.7 1.55 28.1 1.6 ;
        RECT 32.6 1.55 33 1.6 ;
        RECT 37.55 1.55 37.95 1.6 ;
        RECT 0.45 1.25 38.65 1.55 ;
        RECT 3.15 1.2 3.55 1.25 ;
        RECT 8.05 1.2 8.45 1.25 ;
        RECT 12.95 1.2 13.35 1.25 ;
        RECT 17.85 1.2 18.25 1.25 ;
        RECT 22.75 1.2 23.15 1.25 ;
        RECT 27.7 1.2 28.1 1.25 ;
        RECT 32.6 1.2 33 1.25 ;
        RECT 37.55 1.2 37.95 1.25 ;
      LAYER met2 ;
        RECT 0 32.5 0.4 32.9 ;
        RECT 0 28.3 0.3 32.5 ;
        RECT 0.45 30.95 0.85 31.35 ;
        RECT 0 27.9 0.4 28.3 ;
        RECT 0 23.7 0.3 27.9 ;
        RECT 0.55 26.75 0.85 30.95 ;
        RECT 3.7 30.7 4.1 31.1 ;
        RECT 5.35 30.95 5.75 31.35 ;
        RECT 3.15 29.2 3.55 29.6 ;
        RECT 0.45 26.35 0.85 26.75 ;
        RECT 0 23.3 0.4 23.7 ;
        RECT 0 19.2 0.3 23.3 ;
        RECT 0.55 22.2 0.85 26.35 ;
        RECT 3.2 25 3.5 29.2 ;
        RECT 3.8 26.5 4.1 30.7 ;
        RECT 5.45 26.75 5.75 30.95 ;
        RECT 8.6 30.7 9 31.1 ;
        RECT 10.25 30.95 10.65 31.35 ;
        RECT 3.7 26.1 4.1 26.5 ;
        RECT 5.35 26.35 5.75 26.75 ;
        RECT 8.7 26.5 9 30.7 ;
        RECT 10.35 26.75 10.65 30.95 ;
        RECT 13.5 30.7 13.9 31.1 ;
        RECT 15.15 30.95 15.55 31.35 ;
        RECT 3.15 24.6 3.55 25 ;
        RECT 0.45 21.7 0.95 22.2 ;
        RECT 0 18.8 0.4 19.2 ;
        RECT 0 11 0.3 18.8 ;
        RECT 0.55 17.7 0.85 21.7 ;
        RECT 3.2 20.4 3.5 24.6 ;
        RECT 3.8 21.9 4.1 26.1 ;
        RECT 5.45 22.15 5.75 26.35 ;
        RECT 8.6 26.1 9 26.5 ;
        RECT 10.25 26.35 10.65 26.75 ;
        RECT 13.6 26.5 13.9 30.7 ;
        RECT 15.25 26.75 15.55 30.95 ;
        RECT 18.4 30.7 18.8 31.1 ;
        RECT 20.05 30.95 20.45 31.35 ;
        RECT 3.7 21.5 4.1 21.9 ;
        RECT 5.35 21.75 5.8 22.15 ;
        RECT 8.7 21.9 9 26.1 ;
        RECT 10.35 22.15 10.65 26.35 ;
        RECT 13.5 26.1 13.9 26.5 ;
        RECT 15.15 26.35 15.55 26.75 ;
        RECT 18.5 26.5 18.8 30.7 ;
        RECT 20.15 26.75 20.45 30.95 ;
        RECT 23.3 30.7 23.7 31.1 ;
        RECT 25 30.95 25.4 31.35 ;
        RECT 3.15 20 3.55 20.4 ;
        RECT 0.45 17.2 1 17.7 ;
        RECT 0.6 12.35 0.9 17.2 ;
        RECT 3.2 15.9 3.5 20 ;
        RECT 3.8 17.45 4.1 21.5 ;
        RECT 4.9 18.8 5.3 19.2 ;
        RECT 3.7 16.95 4.2 17.45 ;
        RECT 3.15 15.5 3.55 15.9 ;
        RECT 3.2 13.4 3.5 15.5 ;
        RECT 3.15 13 3.55 13.4 ;
        RECT 0.45 11.85 0.95 12.35 ;
        RECT 0 10.6 0.4 11 ;
        RECT 0 5.1 0.3 10.6 ;
        RECT 0.6 8 0.9 11.85 ;
        RECT 2.55 8 2.95 8.05 ;
        RECT 0.6 7.7 2.95 8 ;
        RECT 0 4.7 0.4 5.1 ;
        RECT 0.6 3.8 0.9 7.7 ;
        RECT 2.55 7.65 2.95 7.7 ;
        RECT 3.2 6.3 3.5 13 ;
        RECT 3.8 12.65 4.05 16.95 ;
        RECT 4.9 15.25 5.2 18.8 ;
        RECT 5.45 17.7 5.75 21.75 ;
        RECT 8.6 21.5 9 21.9 ;
        RECT 10.25 21.75 10.65 22.15 ;
        RECT 13.6 21.9 13.9 26.1 ;
        RECT 15.25 22.15 15.55 26.35 ;
        RECT 18.4 26.1 18.8 26.5 ;
        RECT 20.05 26.35 20.45 26.75 ;
        RECT 23.4 26.5 23.7 30.7 ;
        RECT 25.1 26.75 25.4 30.95 ;
        RECT 28.25 30.7 28.65 31.1 ;
        RECT 29.9 30.95 30.3 31.35 ;
        RECT 5.35 17.2 5.9 17.7 ;
        RECT 8.7 17.45 9 21.5 ;
        RECT 9.8 18.8 10.2 19.2 ;
        RECT 4.3 14.95 5.2 15.25 ;
        RECT 3.7 12.15 4.2 12.65 ;
        RECT 3.8 8.65 4.05 12.15 ;
        RECT 4.9 11 5.2 14.95 ;
        RECT 5.5 12.35 5.8 17.2 ;
        RECT 8.6 16.95 9.1 17.45 ;
        RECT 8.05 15.5 8.45 15.9 ;
        RECT 8.1 13.4 8.4 15.5 ;
        RECT 8.05 13 8.45 13.4 ;
        RECT 5.35 11.85 5.85 12.35 ;
        RECT 4.9 10.6 5.3 11 ;
        RECT 3.8 8.3 4.45 8.65 ;
        RECT 4.05 8.25 4.45 8.3 ;
        RECT 3.15 5.9 3.55 6.3 ;
        RECT 0.55 3.4 0.95 3.8 ;
        RECT 0.55 2.8 0.95 3.2 ;
        RECT 3.2 1.6 3.5 5.9 ;
        RECT 4.9 5.1 5.2 10.6 ;
        RECT 5.5 8 5.8 11.85 ;
        RECT 7.45 8 7.85 8.05 ;
        RECT 5.5 7.7 7.85 8 ;
        RECT 4.9 4.7 5.3 5.1 ;
        RECT 5.5 3.8 5.8 7.7 ;
        RECT 7.45 7.65 7.85 7.7 ;
        RECT 8.1 6.3 8.4 13 ;
        RECT 8.7 12.65 8.95 16.95 ;
        RECT 8.6 12.15 9.1 12.65 ;
        RECT 8.7 8.65 8.95 12.15 ;
        RECT 9.8 11 10.1 18.8 ;
        RECT 10.35 17.7 10.65 21.75 ;
        RECT 13.5 21.5 13.9 21.9 ;
        RECT 15.15 21.75 15.55 22.15 ;
        RECT 18.5 21.9 18.8 26.1 ;
        RECT 20.15 22.15 20.45 26.35 ;
        RECT 23.3 26.1 23.7 26.5 ;
        RECT 25 26.35 25.4 26.75 ;
        RECT 28.35 26.5 28.65 30.7 ;
        RECT 30 26.75 30.3 30.95 ;
        RECT 33.15 30.7 33.55 31.1 ;
        RECT 34.85 30.95 35.25 31.35 ;
        RECT 10.25 17.2 10.8 17.7 ;
        RECT 13.6 17.45 13.9 21.5 ;
        RECT 14.7 18.8 15.1 19.2 ;
        RECT 10.4 12.35 10.7 17.2 ;
        RECT 13.5 16.95 14 17.45 ;
        RECT 12.95 15.5 13.35 15.9 ;
        RECT 13 13.4 13.3 15.5 ;
        RECT 12.95 13 13.35 13.4 ;
        RECT 10.25 11.85 10.75 12.35 ;
        RECT 9.8 10.6 10.2 11 ;
        RECT 8.7 8.3 9.35 8.65 ;
        RECT 8.95 8.25 9.35 8.3 ;
        RECT 8.05 5.9 8.45 6.3 ;
        RECT 3.7 3.25 4.15 3.7 ;
        RECT 5.45 3.4 5.85 3.8 ;
        RECT 5.45 2.8 5.85 3.2 ;
        RECT 8.1 1.6 8.4 5.9 ;
        RECT 9.8 5.1 10.1 10.6 ;
        RECT 10.4 8 10.7 11.85 ;
        RECT 12.35 8 12.75 8.05 ;
        RECT 10.4 7.7 12.75 8 ;
        RECT 9.8 4.7 10.2 5.1 ;
        RECT 10.4 3.8 10.7 7.7 ;
        RECT 12.35 7.65 12.75 7.7 ;
        RECT 13 6.3 13.3 13 ;
        RECT 13.6 12.65 13.85 16.95 ;
        RECT 13.5 12.15 14 12.65 ;
        RECT 13.6 8.65 13.85 12.15 ;
        RECT 14.7 11 15 18.8 ;
        RECT 15.25 17.7 15.55 21.75 ;
        RECT 18.4 21.5 18.8 21.9 ;
        RECT 20.05 21.75 20.45 22.15 ;
        RECT 23.4 21.9 23.7 26.1 ;
        RECT 25.1 22.15 25.4 26.35 ;
        RECT 28.25 26.1 28.65 26.5 ;
        RECT 29.9 26.35 30.3 26.75 ;
        RECT 33.25 26.5 33.55 30.7 ;
        RECT 34.95 26.75 35.25 30.95 ;
        RECT 38.1 30.7 38.5 31.1 ;
        RECT 15.15 17.2 15.7 17.7 ;
        RECT 18.5 17.45 18.8 21.5 ;
        RECT 19.6 18.8 20 19.2 ;
        RECT 15.3 12.35 15.6 17.2 ;
        RECT 18.4 16.95 18.9 17.45 ;
        RECT 17.85 15.5 18.25 15.9 ;
        RECT 17.9 13.4 18.2 15.5 ;
        RECT 17.85 13 18.25 13.4 ;
        RECT 15.15 11.85 15.65 12.35 ;
        RECT 14.7 10.6 15.1 11 ;
        RECT 13.6 8.3 14.25 8.65 ;
        RECT 13.85 8.25 14.25 8.3 ;
        RECT 12.95 5.9 13.35 6.3 ;
        RECT 8.6 3.25 9.05 3.7 ;
        RECT 10.35 3.4 10.75 3.8 ;
        RECT 10.35 2.8 10.75 3.2 ;
        RECT 13 1.6 13.3 5.9 ;
        RECT 14.7 5.1 15 10.6 ;
        RECT 15.3 8 15.6 11.85 ;
        RECT 17.25 8 17.65 8.05 ;
        RECT 15.3 7.7 17.65 8 ;
        RECT 14.7 4.7 15.1 5.1 ;
        RECT 15.3 3.8 15.6 7.7 ;
        RECT 17.25 7.65 17.65 7.7 ;
        RECT 17.9 6.3 18.2 13 ;
        RECT 18.5 12.65 18.75 16.95 ;
        RECT 18.4 12.15 18.9 12.65 ;
        RECT 18.5 8.65 18.75 12.15 ;
        RECT 19.6 11 19.9 18.8 ;
        RECT 20.15 17.7 20.45 21.75 ;
        RECT 23.3 21.5 23.7 21.9 ;
        RECT 25 21.75 25.4 22.15 ;
        RECT 28.35 21.9 28.65 26.1 ;
        RECT 30 22.15 30.3 26.35 ;
        RECT 33.15 26.1 33.55 26.5 ;
        RECT 34.85 26.35 35.25 26.75 ;
        RECT 38.2 26.5 38.5 30.7 ;
        RECT 20.05 17.2 20.6 17.7 ;
        RECT 23.4 17.45 23.7 21.5 ;
        RECT 24.55 18.8 24.95 19.2 ;
        RECT 20.2 12.35 20.5 17.2 ;
        RECT 23.3 16.95 23.8 17.45 ;
        RECT 22.75 15.5 23.15 15.9 ;
        RECT 22.8 13.4 23.1 15.5 ;
        RECT 22.75 13 23.15 13.4 ;
        RECT 20.05 11.85 20.55 12.35 ;
        RECT 19.6 10.6 20 11 ;
        RECT 18.5 8.3 19.15 8.65 ;
        RECT 18.75 8.25 19.15 8.3 ;
        RECT 17.85 5.9 18.25 6.3 ;
        RECT 13.5 3.25 13.95 3.7 ;
        RECT 15.25 3.4 15.65 3.8 ;
        RECT 15.25 2.8 15.65 3.2 ;
        RECT 17.9 1.6 18.2 5.9 ;
        RECT 19.6 5.1 19.9 10.6 ;
        RECT 20.2 8 20.5 11.85 ;
        RECT 22.15 8 22.55 8.05 ;
        RECT 20.2 7.7 22.55 8 ;
        RECT 19.6 4.7 20 5.1 ;
        RECT 20.2 3.8 20.5 7.7 ;
        RECT 22.15 7.65 22.55 7.7 ;
        RECT 22.8 6.3 23.1 13 ;
        RECT 23.4 12.65 23.65 16.95 ;
        RECT 23.3 12.15 23.8 12.65 ;
        RECT 23.4 8.65 23.65 12.15 ;
        RECT 24.55 11 24.85 18.8 ;
        RECT 25.1 17.7 25.4 21.75 ;
        RECT 28.25 21.5 28.65 21.9 ;
        RECT 29.9 21.75 30.3 22.15 ;
        RECT 33.25 21.9 33.55 26.1 ;
        RECT 34.95 22.15 35.25 26.35 ;
        RECT 38.1 26.1 38.5 26.5 ;
        RECT 25 17.2 25.55 17.7 ;
        RECT 28.35 17.45 28.65 21.5 ;
        RECT 29.45 18.8 29.85 19.2 ;
        RECT 25.15 12.35 25.45 17.2 ;
        RECT 28.25 16.95 28.75 17.45 ;
        RECT 27.7 15.5 28.1 15.9 ;
        RECT 27.75 13.4 28.05 15.5 ;
        RECT 27.7 13 28.1 13.4 ;
        RECT 25 11.85 25.5 12.35 ;
        RECT 24.55 10.6 24.95 11 ;
        RECT 23.4 8.3 24.05 8.65 ;
        RECT 23.65 8.25 24.05 8.3 ;
        RECT 22.75 5.9 23.15 6.3 ;
        RECT 18.4 3.25 18.85 3.7 ;
        RECT 20.15 3.4 20.55 3.8 ;
        RECT 20.15 2.8 20.55 3.2 ;
        RECT 22.8 1.6 23.1 5.9 ;
        RECT 24.55 5.1 24.85 10.6 ;
        RECT 25.15 8 25.45 11.85 ;
        RECT 27.1 8 27.5 8.05 ;
        RECT 25.15 7.7 27.5 8 ;
        RECT 24.55 4.7 24.95 5.1 ;
        RECT 25.15 3.8 25.45 7.7 ;
        RECT 27.1 7.65 27.5 7.7 ;
        RECT 27.75 6.3 28.05 13 ;
        RECT 28.35 12.65 28.6 16.95 ;
        RECT 28.25 12.15 28.75 12.65 ;
        RECT 28.35 8.65 28.6 12.15 ;
        RECT 29.45 11 29.75 18.8 ;
        RECT 30 17.7 30.3 21.75 ;
        RECT 33.15 21.5 33.55 21.9 ;
        RECT 34.85 21.75 35.25 22.15 ;
        RECT 38.2 21.9 38.5 26.1 ;
        RECT 29.9 17.2 30.45 17.7 ;
        RECT 33.25 17.45 33.55 21.5 ;
        RECT 34.4 18.8 34.8 19.2 ;
        RECT 30.05 12.35 30.35 17.2 ;
        RECT 33.15 16.95 33.65 17.45 ;
        RECT 32.6 15.5 33 15.9 ;
        RECT 32.65 13.4 32.95 15.5 ;
        RECT 32.6 13 33 13.4 ;
        RECT 29.9 11.85 30.4 12.35 ;
        RECT 29.45 10.6 29.85 11 ;
        RECT 28.35 8.3 29 8.65 ;
        RECT 28.6 8.25 29 8.3 ;
        RECT 27.7 5.9 28.1 6.3 ;
        RECT 23.3 3.25 23.75 3.7 ;
        RECT 25.1 3.4 25.5 3.8 ;
        RECT 25.1 2.8 25.5 3.2 ;
        RECT 27.75 1.6 28.05 5.9 ;
        RECT 29.45 5.1 29.75 10.6 ;
        RECT 30.05 8 30.35 11.85 ;
        RECT 32 8 32.4 8.05 ;
        RECT 30.05 7.7 32.4 8 ;
        RECT 29.45 4.7 29.85 5.1 ;
        RECT 30.05 3.8 30.35 7.7 ;
        RECT 32 7.65 32.4 7.7 ;
        RECT 32.65 6.3 32.95 13 ;
        RECT 33.25 12.65 33.5 16.95 ;
        RECT 33.15 12.15 33.65 12.65 ;
        RECT 33.25 8.65 33.5 12.15 ;
        RECT 34.4 11 34.7 18.8 ;
        RECT 34.95 17.7 35.25 21.75 ;
        RECT 38.1 21.5 38.5 21.9 ;
        RECT 34.85 17.2 35.4 17.7 ;
        RECT 38.2 17.45 38.5 21.5 ;
        RECT 35 12.35 35.3 17.2 ;
        RECT 38.1 16.95 38.6 17.45 ;
        RECT 37.55 15.5 37.95 15.9 ;
        RECT 37.6 13.4 37.9 15.5 ;
        RECT 37.55 13 37.95 13.4 ;
        RECT 34.85 11.85 35.35 12.35 ;
        RECT 34.4 10.6 34.8 11 ;
        RECT 33.25 8.3 33.9 8.65 ;
        RECT 33.5 8.25 33.9 8.3 ;
        RECT 32.6 5.9 33 6.3 ;
        RECT 28.25 3.25 28.7 3.7 ;
        RECT 30 3.4 30.4 3.8 ;
        RECT 30 2.8 30.4 3.2 ;
        RECT 32.65 1.6 32.95 5.9 ;
        RECT 34.4 5.1 34.7 10.6 ;
        RECT 35 8 35.3 11.85 ;
        RECT 36.95 8 37.35 8.05 ;
        RECT 35 7.7 37.35 8 ;
        RECT 34.4 4.7 34.8 5.1 ;
        RECT 35 3.8 35.3 7.7 ;
        RECT 36.95 7.65 37.35 7.7 ;
        RECT 37.6 6.3 37.9 13 ;
        RECT 38.2 12.65 38.45 16.95 ;
        RECT 38.1 12.15 38.6 12.65 ;
        RECT 38.2 8.65 38.45 12.15 ;
        RECT 38.2 8.3 38.85 8.65 ;
        RECT 38.45 8.25 38.85 8.3 ;
        RECT 37.55 5.9 37.95 6.3 ;
        RECT 33.15 3.25 33.6 3.7 ;
        RECT 34.95 3.4 35.35 3.8 ;
        RECT 34.95 2.8 35.35 3.2 ;
        RECT 37.6 1.6 37.9 5.9 ;
        RECT 38.1 3.25 38.55 3.7 ;
        RECT 3.15 1.2 3.55 1.6 ;
        RECT 8.05 1.2 8.45 1.6 ;
        RECT 12.95 1.2 13.35 1.6 ;
        RECT 17.85 1.2 18.25 1.6 ;
        RECT 22.75 1.2 23.15 1.6 ;
        RECT 27.7 1.2 28.1 1.6 ;
        RECT 32.6 1.2 33 1.6 ;
        RECT 37.55 1.2 37.95 1.6 ;
      LAYER met3 ;
        RECT -2.4 5.45 -1.15 6.7 ;
        RECT -2.4 3.15 -1.15 4.4 ;
        RECT 40.1 3.15 41.35 4.4 ;
        RECT -2.4 0.85 -1.15 2.1 ;
        RECT 40.1 0.85 41.35 2.1 ;
  END
END Array_4x8_non_hiera_Pin
END LIBRARY

